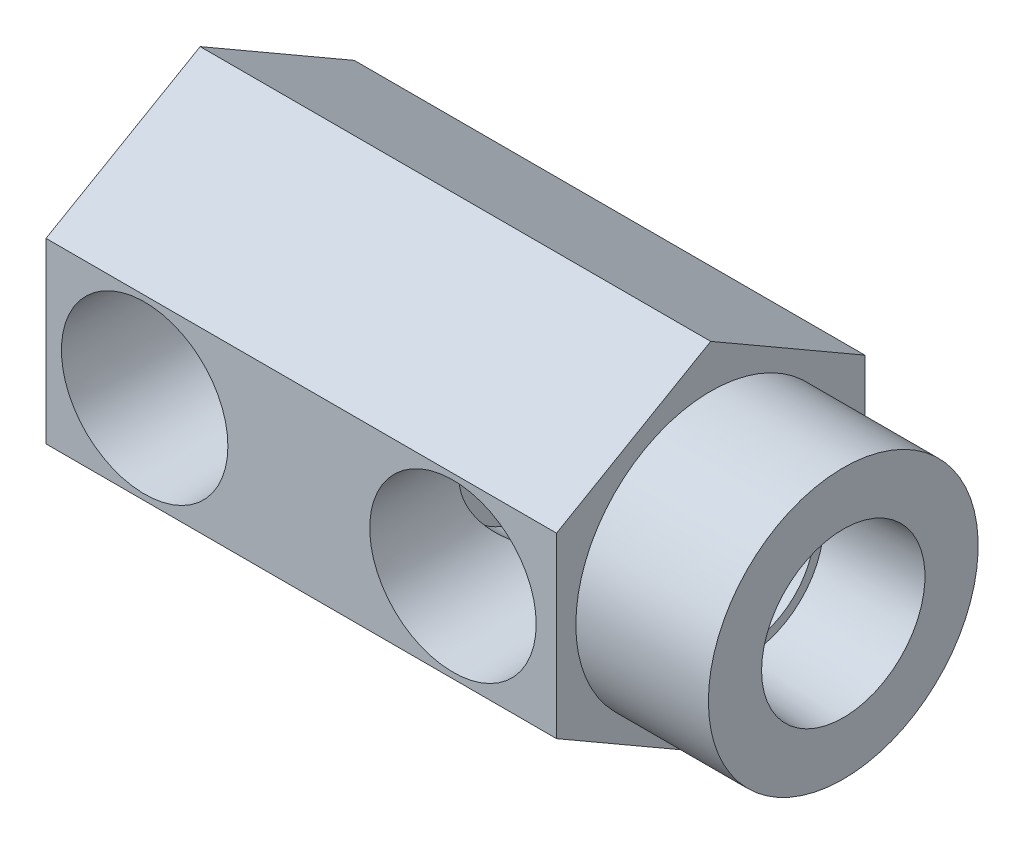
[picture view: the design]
ISO-10303-21;
HEADER;
FILE_DESCRIPTION(('STEP AP214'),'2;1');
FILE_NAME('part.step','',(''),(''),'','','');
FILE_SCHEMA(('AUTOMOTIVE_DESIGN { 1 0 10303 214 1 1 1 1 }'));
ENDSEC;
DATA;
#1=APPLICATION_CONTEXT('core data for automotive mechanical design processes');
#2=APPLICATION_PROTOCOL_DEFINITION('international standard','automotive_design',2000,#1);
#3=PRODUCT_CONTEXT('',#1,'mechanical');
#4=PRODUCT('Part','Part','',(#3));
#5=PRODUCT_RELATED_PRODUCT_CATEGORY('part','',(#4));
#6=PRODUCT_DEFINITION_FORMATION('','',#4);
#7=PRODUCT_DEFINITION_CONTEXT('part definition',#1,'design');
#8=PRODUCT_DEFINITION('design','',#6,#7);
#9=PRODUCT_DEFINITION_SHAPE('','',#8);
#10=(LENGTH_UNIT() NAMED_UNIT(*) SI_UNIT(.MILLI.,.METRE.));
#11=(NAMED_UNIT(*) PLANE_ANGLE_UNIT() SI_UNIT($,.RADIAN.));
#12=(NAMED_UNIT(*) SI_UNIT($,.STERADIAN.) SOLID_ANGLE_UNIT());
#13=UNCERTAINTY_MEASURE_WITH_UNIT(LENGTH_MEASURE(1.E-05),#10,'distance_accuracy_value','');
#14=(GEOMETRIC_REPRESENTATION_CONTEXT(3) GLOBAL_UNCERTAINTY_ASSIGNED_CONTEXT((#13)) GLOBAL_UNIT_ASSIGNED_CONTEXT((#10,
#11,#12)) REPRESENTATION_CONTEXT('',''));
#15=CARTESIAN_POINT('',(0.,0.,0.));
#16=DIRECTION('',(0.,0.,1.));
#17=DIRECTION('',(1.,0.,0.));
#18=AXIS2_PLACEMENT_3D('',#15,#16,#17);
#19=CARTESIAN_POINT('',(52.9844,0.,0.));
#20=DIRECTION('',(1.,0.,0.));
#21=DIRECTION('',(0.,0.,-1.));
#22=AXIS2_PLACEMENT_3D('',#19,#20,#21);
#23=CYLINDRICAL_SURFACE('',#22,3.17499999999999);
#24=CARTESIAN_POINT('',(16.4084,0.,0.));
#25=DIRECTION('',(1.,0.,0.));
#26=DIRECTION('',(0.,0.,-1.));
#27=AXIS2_PLACEMENT_3D('',#24,#25,#26);
#28=CIRCLE('',#27,3.17499999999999);
#29=CARTESIAN_POINT('',(16.4084,0.,-3.17499999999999));
#30=VERTEX_POINT('',#29);
#31=EDGE_CURVE('E172',#30,#30,#28,.T.);
#32=ORIENTED_EDGE('',*,*,#31,.F.);
#33=EDGE_LOOP('',(#32));
#34=FACE_BOUND('',#33,.T.);
#35=CARTESIAN_POINT('',(26.79065,0.,0.));
#36=DIRECTION('',(1.,0.,0.));
#37=DIRECTION('',(0.,0.,-1.));
#38=AXIS2_PLACEMENT_3D('',#35,#36,#37);
#39=CIRCLE('',#38,3.17499999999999);
#40=CARTESIAN_POINT('',(26.79065,0.,-3.17499999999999));
#41=VERTEX_POINT('',#40);
#42=EDGE_CURVE('E39',#41,#41,#39,.F.);
#43=ORIENTED_EDGE('',*,*,#42,.F.);
#44=EDGE_LOOP('',(#43));
#45=FACE_BOUND('',#44,.T.);
#46=ADVANCED_FACE('F35',(#34,#45),#23,.F.);
#47=CARTESIAN_POINT('',(39.0906,0.,2.6797));
#48=DIRECTION('',(0.,0.,-1.));
#49=DIRECTION('',(-1.,0.,0.));
#50=AXIS2_PLACEMENT_3D('',#47,#48,#49);
#51=PLANE('',#50);
#52=DIRECTION('',(-1.,0.,0.));
#53=VECTOR('',#52,1.);
#54=CARTESIAN_POINT('',(0.,4.86010266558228,2.6797));
#55=LINE('',#54,#53);
#56=CARTESIAN_POINT('',(37.9310089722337,4.86010266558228,2.6797));
#57=VERTEX_POINT('',#56);
#58=CARTESIAN_POINT('',(36.2339048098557,4.86010266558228,2.6797));
#59=VERTEX_POINT('',#58);
#60=EDGE_CURVE('E442',#57,#59,#55,.T.);
#61=ORIENTED_EDGE('',*,*,#60,.F.);
#62=CARTESIAN_POINT('',(33.528,0.,2.6797));
#63=DIRECTION('',(0.,0.,1.));
#64=DIRECTION('',(1.,0.,0.));
#65=AXIS2_PLACEMENT_3D('',#62,#63,#64);
#66=CIRCLE('',#65,6.55797879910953);
#67=CARTESIAN_POINT('',(29.1249910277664,4.86010266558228,2.6797));
#68=VERTEX_POINT('',#67);
#69=EDGE_CURVE('E424',#57,#68,#66,.T.);
#70=ORIENTED_EDGE('',*,*,#69,.T.);
#71=CARTESIAN_POINT('',(30.8220951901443,4.86010266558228,2.6797));
#72=VERTEX_POINT('',#71);
#73=EDGE_CURVE('E281',#72,#68,#55,.T.);
#74=ORIENTED_EDGE('',*,*,#73,.F.);
#75=CARTESIAN_POINT('',(33.528,0.,2.6797));
#76=DIRECTION('',(0.,0.,1.));
#77=DIRECTION('',(1.,0.,0.));
#78=AXIS2_PLACEMENT_3D('',#75,#76,#77);
#79=CIRCLE('',#78,5.5626);
#80=EDGE_CURVE('E164',#59,#72,#79,.T.);
#81=ORIENTED_EDGE('',*,*,#80,.F.);
#82=EDGE_LOOP('',(#61,#70,#74,#81));
#83=FACE_BOUND('',#82,.T.);
#84=ADVANCED_FACE('F261',(#83),#51,.F.);
#85=DIRECTION('',(-1.,0.,0.));
#86=VECTOR('',#85,1.);
#87=CARTESIAN_POINT('',(0.,-4.86010266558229,2.6797));
#88=LINE('',#87,#86);
#89=CARTESIAN_POINT('',(29.1249910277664,-4.86010266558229,2.6797));
#90=VERTEX_POINT('',#89);
#91=CARTESIAN_POINT('',(30.8220951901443,-4.86010266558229,2.6797));
#92=VERTEX_POINT('',#91);
#93=EDGE_CURVE('E165',#90,#92,#88,.F.);
#94=ORIENTED_EDGE('',*,*,#93,.F.);
#95=CARTESIAN_POINT('',(37.9310089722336,-4.86010266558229,2.6797));
#96=VERTEX_POINT('',#95);
#97=EDGE_CURVE('E420',#90,#96,#66,.T.);
#98=ORIENTED_EDGE('',*,*,#97,.T.);
#99=CARTESIAN_POINT('',(36.2339048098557,-4.86010266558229,2.6797));
#100=VERTEX_POINT('',#99);
#101=EDGE_CURVE('E328',#100,#96,#88,.F.);
#102=ORIENTED_EDGE('',*,*,#101,.F.);
#103=EDGE_CURVE('E430',#92,#100,#79,.T.);
#104=ORIENTED_EDGE('',*,*,#103,.F.);
#105=EDGE_LOOP('',(#94,#98,#102,#104));
#106=FACE_BOUND('',#105,.T.);
#107=ADVANCED_FACE('F331',(#106),#51,.F.);
#108=CARTESIAN_POINT('',(33.528,0.,12.7));
#109=DIRECTION('',(0.,0.,1.));
#110=DIRECTION('',(1.,0.,0.));
#111=AXIS2_PLACEMENT_3D('',#108,#109,#110);
#112=CYLINDRICAL_SURFACE('',#111,5.56260000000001);
#113=CARTESIAN_POINT('',(29.1430778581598,3.42271479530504,-4.3688));
#114=CARTESIAN_POINT('',(29.2053786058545,3.50252392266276,-4.30626922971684));
#115=CARTESIAN_POINT('',(29.2692305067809,3.57983993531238,-4.24217199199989));
#116=CARTESIAN_POINT('',(29.3997001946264,3.72954742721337,-4.111175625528));
#117=CARTESIAN_POINT('',(29.4663169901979,3.80194064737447,-4.0442775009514));
#118=CARTESIAN_POINT('',(29.6696020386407,4.01162562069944,-3.84008739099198));
#119=CARTESIAN_POINT('',(29.8099614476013,4.14174719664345,-3.69904228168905));
#120=CARTESIAN_POINT('',(30.0975597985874,4.38288342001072,-3.40984184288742));
#121=CARTESIAN_POINT('',(30.2447640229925,4.4939834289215,-3.26172230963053));
#122=CARTESIAN_POINT('',(30.5450099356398,4.69864874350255,-2.95929639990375));
#123=CARTESIAN_POINT('',(30.6980539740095,4.79220689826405,-2.80498753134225));
#124=CARTESIAN_POINT('',(30.9831508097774,4.94855700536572,-2.51703491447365));
#125=CARTESIAN_POINT('',(31.1145644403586,5.01387804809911,-2.38411695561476));
#126=CARTESIAN_POINT('',(31.3796036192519,5.13303105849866,-2.11541586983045));
#127=CARTESIAN_POINT('',(31.5132288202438,5.1868648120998,-1.97963319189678));
#128=CARTESIAN_POINT('',(31.7816711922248,5.28329287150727,-1.7056562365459));
#129=CARTESIAN_POINT('',(31.9164866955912,5.32590091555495,-1.56746512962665));
#130=CARTESIAN_POINT('',(32.1863893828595,5.40019502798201,-1.28848056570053));
#131=CARTESIAN_POINT('',(32.3214764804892,5.43188413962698,-1.14768784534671));
#132=CARTESIAN_POINT('',(32.5189904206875,5.47070908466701,-0.936746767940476));
#133=CARTESIAN_POINT('',(32.5823943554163,5.48200911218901,-0.868244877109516));
#134=CARTESIAN_POINT('',(32.7080219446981,5.50219723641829,-0.729494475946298));
#135=CARTESIAN_POINT('',(32.7702429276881,5.51108036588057,-0.659242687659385));
#136=CARTESIAN_POINT('',(32.878517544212,5.5247658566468,-0.530668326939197));
#137=CARTESIAN_POINT('',(32.9252277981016,5.53003323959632,-0.4729291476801));
#138=CARTESIAN_POINT('',(33.0138391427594,5.53895660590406,-0.353523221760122));
#139=CARTESIAN_POINT('',(33.0557550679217,5.54261766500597,-0.291869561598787));
#140=CARTESIAN_POINT('',(33.1029068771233,5.54635110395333,-0.200071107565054));
#141=CARTESIAN_POINT('',(33.1149282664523,5.54725075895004,-0.17362424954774));
#142=CARTESIAN_POINT('',(33.1346806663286,5.54868581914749,-0.11920938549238));
#143=CARTESIAN_POINT('',(33.1424339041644,5.54922311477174,-0.091250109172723));
#144=CARTESIAN_POINT('',(33.1507682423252,5.54979551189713,-0.0406082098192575));
#145=CARTESIAN_POINT('',(33.1525611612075,5.54991574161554,-0.0181354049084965));
#146=CARTESIAN_POINT('',(33.1520473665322,5.5498809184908,0.0267461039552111));
#147=CARTESIAN_POINT('',(33.1497432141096,5.54972603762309,0.0491548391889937));
#148=CARTESIAN_POINT('',(33.1402182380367,5.54906942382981,0.100345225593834));
#149=CARTESIAN_POINT('',(33.1316568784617,5.54847233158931,0.128864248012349));
#150=CARTESIAN_POINT('',(33.1103226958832,5.54690714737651,0.184367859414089));
#151=CARTESIAN_POINT('',(33.0975213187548,5.54593653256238,0.21134054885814));
#152=CARTESIAN_POINT('',(33.0586644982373,5.54281975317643,0.284099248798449));
#153=CARTESIAN_POINT('',(33.0299816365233,5.5403433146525,0.328420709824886));
#154=CARTESIAN_POINT('',(32.9692649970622,5.5345538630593,0.414689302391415));
#155=CARTESIAN_POINT('',(32.9372207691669,5.53123819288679,0.456628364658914));
#156=CARTESIAN_POINT('',(32.8710999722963,5.52377748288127,0.539458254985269));
#157=CARTESIAN_POINT('',(32.8370069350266,5.51962483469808,0.580335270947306));
#158=CARTESIAN_POINT('',(32.7679056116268,5.51053473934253,0.661091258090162));
#159=CARTESIAN_POINT('',(32.7328988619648,5.50559854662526,0.700971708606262));
#160=CARTESIAN_POINT('',(32.6194514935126,5.48846855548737,0.828218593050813));
#161=CARTESIAN_POINT('',(32.5399173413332,5.47474378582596,0.914407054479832));
#162=CARTESIAN_POINT('',(32.3799423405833,5.44345110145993,1.08523802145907));
#163=CARTESIAN_POINT('',(32.2995012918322,5.42588232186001,1.16988017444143));
#164=CARTESIAN_POINT('',(32.0576616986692,5.36731988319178,1.4223942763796));
#165=CARTESIAN_POINT('',(31.8959389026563,5.32049832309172,1.58864694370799));
#166=CARTESIAN_POINT('',(31.5803741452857,5.21306486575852,1.91130379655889));
#167=CARTESIAN_POINT('',(31.4264669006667,5.15304719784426,2.06784173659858));
#168=CARTESIAN_POINT('',(31.1978738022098,5.05172859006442,2.29968019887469));
#169=CARTESIAN_POINT('',(31.1221017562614,5.01610006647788,2.37641685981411));
#170=CARTESIAN_POINT('',(30.9714170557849,4.94100069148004,2.52885627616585));
#171=CARTESIAN_POINT('',(30.89650445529,4.90152959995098,2.60455896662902));
#172=CARTESIAN_POINT('',(30.8220951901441,4.8601026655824,2.67969999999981));
#173=B_SPLINE_CURVE_WITH_KNOTS('',3,(#113,#114,#115,#116,#117,#118,#119,#120,#121,#122,#123,
#124,#125,#126,#127,#128,#129,#130,#131,#132,#133,#134,#135,#136,#137,#138,#139,#140,#141,#142,
#143,#144,#145,#146,#147,#148,#149,#150,#151,#152,#153,#154,#155,#156,#157,#158,#159,#160,#161,
#162,#163,#164,#165,#166,#167,#168,#169,#170,#171,#172),.UNSPECIFIED.,.F.,.F.,(4,2,2,2,2,2,2,2,
2,2,2,2,2,2,2,2,2,2,2,2,2,2,2,2,2,2,2,2,2,4),(0.,0.356890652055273,0.713654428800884,
1.42572741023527,2.13451598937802,2.84359287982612,3.4372250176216,4.03076479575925,
4.6235747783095,5.2162194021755,5.49827347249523,5.78090291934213,6.00433449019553,
6.22705487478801,6.3140330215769,6.40055381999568,6.46782718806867,6.53505851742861,
6.62386536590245,6.71328286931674,6.87138898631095,7.03000208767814,7.19012792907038,
7.34999994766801,7.70411945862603,8.05831872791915,8.7675669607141,9.44975807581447,
9.7904185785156,10.1311003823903),.UNSPECIFIED.);
#174=CARTESIAN_POINT('',(29.1430778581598,3.42271479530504,-4.3688));
#175=VERTEX_POINT('',#174);
#176=EDGE_CURVE('E150',#175,#72,#173,.T.);
#177=ORIENTED_EDGE('',*,*,#176,.F.);
#178=CARTESIAN_POINT('',(33.528,0.,-4.3688));
#179=DIRECTION('',(0.,0.,1.));
#180=DIRECTION('',(1.,0.,0.));
#181=AXIS2_PLACEMENT_3D('',#178,#179,#180);
#182=CIRCLE('',#181,5.56260000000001);
#183=CARTESIAN_POINT('',(37.9129221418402,3.42271479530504,-4.3688));
#184=VERTEX_POINT('',#183);
#185=EDGE_CURVE('E162',#184,#175,#182,.T.);
#186=ORIENTED_EDGE('',*,*,#185,.F.);
#187=CARTESIAN_POINT('',(36.2339048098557,4.86010266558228,2.6797));
#188=CARTESIAN_POINT('',(36.1573626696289,4.90271691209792,2.6024048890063));
#189=CARTESIAN_POINT('',(36.0802883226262,4.94326160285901,2.52451611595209));
#190=CARTESIAN_POINT('',(35.9252343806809,5.02028696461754,2.36764700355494));
#191=CARTESIAN_POINT('',(35.8472548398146,5.05676787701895,2.28866672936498));
#192=CARTESIAN_POINT('',(35.6120714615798,5.16028405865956,2.05010484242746));
#193=CARTESIAN_POINT('',(35.4537326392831,5.22133212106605,1.88901283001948));
#194=CARTESIAN_POINT('',(35.1345730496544,5.32821249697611,1.56246076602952));
#195=CARTESIAN_POINT('',(34.9737434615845,5.37396013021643,1.39698170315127));
#196=CARTESIAN_POINT('',(34.7333316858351,5.43106765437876,1.14553430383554));
#197=CARTESIAN_POINT('',(34.6533574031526,5.44818105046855,1.06120651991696));
#198=CARTESIAN_POINT('',(34.4943992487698,5.47860389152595,0.890954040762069));
#199=CARTESIAN_POINT('',(34.4154151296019,5.49191430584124,0.805029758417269));
#200=CARTESIAN_POINT('',(34.2931936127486,5.50990529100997,0.667021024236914));
#201=CARTESIAN_POINT('',(34.2489571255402,5.51585557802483,0.615983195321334));
#202=CARTESIAN_POINT('',(34.1624383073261,5.52647109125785,0.512104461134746));
#203=CARTESIAN_POINT('',(34.1201555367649,5.5311366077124,0.459263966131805));
#204=CARTESIAN_POINT('',(34.0564332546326,5.53749527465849,0.372271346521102));
#205=CARTESIAN_POINT('',(34.033506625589,5.53962582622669,0.339251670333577));
#206=CARTESIAN_POINT('',(33.9905937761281,5.54337271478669,0.271242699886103));
#207=CARTESIAN_POINT('',(33.9706061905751,5.54498929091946,0.236254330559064));
#208=CARTESIAN_POINT('',(33.9426831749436,5.54713245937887,0.176754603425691));
#209=CARTESIAN_POINT('',(33.933013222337,5.54784146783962,0.153090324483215));
#210=CARTESIAN_POINT('',(33.9172951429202,5.54896659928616,0.104612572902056));
#211=CARTESIAN_POINT('',(33.9112335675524,5.54938381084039,0.0798037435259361));
#212=CARTESIAN_POINT('',(33.9039509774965,5.54988255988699,0.029035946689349));
#213=CARTESIAN_POINT('',(33.9028053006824,5.54995887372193,0.00306520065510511));
#214=CARTESIAN_POINT('',(33.9059120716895,5.54974795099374,-0.0485454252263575));
#215=CARTESIAN_POINT('',(33.9101699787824,5.54946034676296,-0.0741849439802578));
#216=CARTESIAN_POINT('',(33.9247955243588,5.54843534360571,-0.131549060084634));
#217=CARTESIAN_POINT('',(33.9365743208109,5.54759189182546,-0.162888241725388));
#218=CARTESIAN_POINT('',(33.9643836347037,5.54547446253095,-0.223685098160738));
#219=CARTESIAN_POINT('',(33.9804398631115,5.54419786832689,-0.25313001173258));
#220=CARTESIAN_POINT('',(34.0343579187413,5.53962508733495,-0.343123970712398));
#221=CARTESIAN_POINT('',(34.0763107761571,5.5356796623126,-0.40110731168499));
#222=CARTESIAN_POINT('',(34.1638595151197,5.52631907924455,-0.51417606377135));
#223=CARTESIAN_POINT('',(34.2094670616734,5.52089907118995,-0.569251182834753));
#224=CARTESIAN_POINT('',(34.3026304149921,5.50860024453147,-0.678027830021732));
#225=CARTESIAN_POINT('',(34.350194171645,5.50171487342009,-0.731721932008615));
#226=CARTESIAN_POINT('',(34.4461025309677,5.48652622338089,-0.838028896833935));
#227=CARTESIAN_POINT('',(34.4944457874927,5.47822519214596,-0.890643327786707));
#228=CARTESIAN_POINT('',(34.6402922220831,5.45115530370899,-1.04766823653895));
#229=CARTESIAN_POINT('',(34.7384665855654,5.43023844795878,-1.15109678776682));
#230=CARTESIAN_POINT('',(34.9351156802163,5.38263989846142,-1.35633654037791));
#231=CARTESIAN_POINT('',(35.033590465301,5.35595710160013,-1.45814742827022));
#232=CARTESIAN_POINT('',(35.3287530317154,5.26707075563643,-1.76179770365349));
#233=CARTESIAN_POINT('',(35.5249600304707,5.19606887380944,-1.96162494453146));
#234=CARTESIAN_POINT('',(35.9119743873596,5.03024468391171,-2.35440015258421));
#235=CARTESIAN_POINT('',(36.1028039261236,4.93554387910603,-2.54737764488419));
#236=CARTESIAN_POINT('',(36.4776329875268,4.72109486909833,-2.92572825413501));
#237=CARTESIAN_POINT('',(36.6616385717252,4.60136955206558,-3.11110813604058));
#238=CARTESIAN_POINT('',(36.9369676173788,4.39724605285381,-3.38822135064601));
#239=CARTESIAN_POINT('',(37.0317095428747,4.3222036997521,-3.48352487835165));
#240=CARTESIAN_POINT('',(37.2179314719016,4.1643506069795,-3.67077145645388));
#241=CARTESIAN_POINT('',(37.3094126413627,4.08154268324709,-3.76271570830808));
#242=CARTESIAN_POINT('',(37.488908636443,3.90760849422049,-3.94306288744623));
#243=CARTESIAN_POINT('',(37.5769089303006,3.81645174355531,-4.03145099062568));
#244=CARTESIAN_POINT('',(37.748455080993,3.62583915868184,-4.20370936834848));
#245=CARTESIAN_POINT('',(37.8319969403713,3.52637607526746,-4.28757558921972));
#246=CARTESIAN_POINT('',(37.9129221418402,3.42271479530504,-4.3688));
#247=B_SPLINE_CURVE_WITH_KNOTS('',3,(#187,#188,#189,#190,#191,#192,#193,#194,#195,#196,#197,
#198,#199,#200,#201,#202,#203,#204,#205,#206,#207,#208,#209,#210,#211,#212,#213,#214,#215,#216,
#217,#218,#219,#220,#221,#222,#223,#224,#225,#226,#227,#228,#229,#230,#231,#232,#233,#234,#235,
#236,#237,#238,#239,#240,#241,#242,#243,#244,#245,#246),.UNSPECIFIED.,.F.,.F.,(4,2,2,2,2,2,2,2,
2,2,2,2,2,2,2,2,2,2,2,2,2,2,2,2,2,2,2,2,2,4),(0.,0.350444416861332,0.700868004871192,
1.4022157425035,2.10738322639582,2.45975259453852,2.8120320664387,3.01541959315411,
3.21876113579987,3.33946287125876,3.46010836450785,3.53663938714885,3.61288336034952,
3.69029171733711,3.7677783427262,3.8676813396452,3.9681989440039,4.18262718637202,
4.39776940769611,4.61389466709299,4.82967991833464,5.26190889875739,5.69422064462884,
6.55980087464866,7.42103111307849,8.28147706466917,8.74300288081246,9.20436198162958,
9.66747853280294,10.1310035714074),.UNSPECIFIED.);
#248=EDGE_CURVE('E58',#59,#184,#247,.T.);
#249=ORIENTED_EDGE('',*,*,#248,.F.);
#250=ORIENTED_EDGE('',*,*,#80,.T.);
#251=EDGE_LOOP('',(#177,#186,#249,#250));
#252=FACE_BOUND('',#251,.T.);
#253=ADVANCED_FACE('F161',(#252),#112,.F.);
#254=CARTESIAN_POINT('',(37.9129221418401,-3.42271479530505,-4.3688));
#255=CARTESIAN_POINT('',(37.8506213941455,-3.50252392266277,-4.30626922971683));
#256=CARTESIAN_POINT('',(37.7867694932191,-3.57983993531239,-4.24217199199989));
#257=CARTESIAN_POINT('',(37.6562998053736,-3.72954742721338,-4.111175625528));
#258=CARTESIAN_POINT('',(37.5896830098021,-3.80194064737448,-4.0442775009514));
#259=CARTESIAN_POINT('',(37.3863979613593,-4.01162562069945,-3.84008739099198));
#260=CARTESIAN_POINT('',(37.2460385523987,-4.14174719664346,-3.69904228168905));
#261=CARTESIAN_POINT('',(36.9584402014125,-4.38288342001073,-3.40984184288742));
#262=CARTESIAN_POINT('',(36.8112359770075,-4.49398342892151,-3.26172230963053));
#263=CARTESIAN_POINT('',(36.5109900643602,-4.69864874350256,-2.95929639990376));
#264=CARTESIAN_POINT('',(36.3579460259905,-4.79220689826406,-2.80498753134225));
#265=CARTESIAN_POINT('',(36.0728491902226,-4.94855700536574,-2.51703491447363));
#266=CARTESIAN_POINT('',(35.9414355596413,-5.01387804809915,-2.38411695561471));
#267=CARTESIAN_POINT('',(35.676396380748,-5.13303105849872,-2.11541586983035));
#268=CARTESIAN_POINT('',(35.5427711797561,-5.18686481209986,-1.97963319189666));
#269=CARTESIAN_POINT('',(35.274328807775,-5.28329287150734,-1.70565623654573));
#270=CARTESIAN_POINT('',(35.1395133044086,-5.32590091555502,-1.56746512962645));
#271=CARTESIAN_POINT('',(34.8696106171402,-5.40019502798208,-1.28848056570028));
#272=CARTESIAN_POINT('',(34.7345235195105,-5.43188413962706,-1.14768784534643));
#273=CARTESIAN_POINT('',(34.5370095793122,-5.47070908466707,-0.936746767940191));
#274=CARTESIAN_POINT('',(34.4736056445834,-5.48200911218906,-0.868244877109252));
#275=CARTESIAN_POINT('',(34.3479780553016,-5.50219723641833,-0.729494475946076));
#276=CARTESIAN_POINT('',(34.2857570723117,-5.51108036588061,-0.659242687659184));
#277=CARTESIAN_POINT('',(34.1774824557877,-5.52476585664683,-0.530668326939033));
#278=CARTESIAN_POINT('',(34.1307722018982,-5.53003323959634,-0.472929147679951));
#279=CARTESIAN_POINT('',(34.0421608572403,-5.53895660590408,-0.353523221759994));
#280=CARTESIAN_POINT('',(34.0002449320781,-5.54261766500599,-0.291869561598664));
#281=CARTESIAN_POINT('',(33.9530931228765,-5.54635110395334,-0.200071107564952));
#282=CARTESIAN_POINT('',(33.9410717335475,-5.54725075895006,-0.173624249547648));
#283=CARTESIAN_POINT('',(33.9213193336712,-5.5486858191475,-0.119209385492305));
#284=CARTESIAN_POINT('',(33.9135660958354,-5.54922311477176,-0.0912501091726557));
#285=CARTESIAN_POINT('',(33.9052317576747,-5.54979551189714,-0.040608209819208));
#286=CARTESIAN_POINT('',(33.9034388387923,-5.54991574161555,-0.0181354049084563));
#287=CARTESIAN_POINT('',(33.9039526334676,-5.54988091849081,0.0267461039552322));
#288=CARTESIAN_POINT('',(33.9062567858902,-5.5497260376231,0.049154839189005));
#289=CARTESIAN_POINT('',(33.9157817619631,-5.54906942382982,0.100345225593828));
#290=CARTESIAN_POINT('',(33.9243431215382,-5.54847233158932,0.128864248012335));
#291=CARTESIAN_POINT('',(33.9456773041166,-5.54690714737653,0.184367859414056));
#292=CARTESIAN_POINT('',(33.9584786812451,-5.54593653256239,0.211340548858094));
#293=CARTESIAN_POINT('',(33.9973355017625,-5.54281975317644,0.284099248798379));
#294=CARTESIAN_POINT('',(34.0260183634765,-5.54034331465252,0.328420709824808));
#295=CARTESIAN_POINT('',(34.0867350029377,-5.53455386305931,0.414689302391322));
#296=CARTESIAN_POINT('',(34.1187792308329,-5.53123819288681,0.456628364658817));
#297=CARTESIAN_POINT('',(34.1849000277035,-5.5237774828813,0.539458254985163));
#298=CARTESIAN_POINT('',(34.2189930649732,-5.5196248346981,0.580335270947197));
#299=CARTESIAN_POINT('',(34.288094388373,-5.51053473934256,0.66109125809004));
#300=CARTESIAN_POINT('',(34.323101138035,-5.50559854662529,0.700971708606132));
#301=CARTESIAN_POINT('',(34.4365485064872,-5.4884685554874,0.828218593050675));
#302=CARTESIAN_POINT('',(34.5160826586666,-5.474743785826,0.914407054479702));
#303=CARTESIAN_POINT('',(34.6760576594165,-5.44345110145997,1.08523802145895));
#304=CARTESIAN_POINT('',(34.7564987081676,-5.42588232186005,1.16988017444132));
#305=CARTESIAN_POINT('',(34.9983383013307,-5.36731988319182,1.4223942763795));
#306=CARTESIAN_POINT('',(35.1600610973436,-5.32049832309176,1.58864694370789));
#307=CARTESIAN_POINT('',(35.4756258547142,-5.21306486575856,1.91130379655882));
#308=CARTESIAN_POINT('',(35.6295330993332,-5.1530471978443,2.06784173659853));
#309=CARTESIAN_POINT('',(35.8581261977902,-5.05172859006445,2.29968019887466));
#310=CARTESIAN_POINT('',(35.9338982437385,-5.0161000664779,2.37641685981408));
#311=CARTESIAN_POINT('',(36.084582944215,-4.94100069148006,2.52885627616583));
#312=CARTESIAN_POINT('',(36.1594955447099,-4.901529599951,2.60455896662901));
#313=CARTESIAN_POINT('',(36.2339048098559,-4.86010266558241,2.67969999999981));
#314=B_SPLINE_CURVE_WITH_KNOTS('',3,(#254,#255,#256,#257,#258,#259,#260,#261,#262,#263,#264,
#265,#266,#267,#268,#269,#270,#271,#272,#273,#274,#275,#276,#277,#278,#279,#280,#281,#282,#283,
#284,#285,#286,#287,#288,#289,#290,#291,#292,#293,#294,#295,#296,#297,#298,#299,#300,#301,#302,
#303,#304,#305,#306,#307,#308,#309,#310,#311,#312,#313),.UNSPECIFIED.,.F.,.F.,(4,2,2,2,2,2,2,2,
2,2,2,2,2,2,2,2,2,2,2,2,2,2,2,2,2,2,2,2,2,4),(0.,0.356890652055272,0.713654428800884,
1.42572741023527,2.13451598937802,2.84359287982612,3.43722501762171,4.03076479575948,
4.62357477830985,5.21621940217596,5.49827347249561,5.78090291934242,6.00433449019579,
6.22705487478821,6.31403302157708,6.40055381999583,6.4678271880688,6.53505851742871,
6.62386536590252,6.71328286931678,6.87138898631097,7.03000208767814,7.19012792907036,
7.34999994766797,7.70411945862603,8.05831872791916,8.76756696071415,9.44975807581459,
9.79041857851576,10.1311003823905),.UNSPECIFIED.);
#315=CARTESIAN_POINT('',(37.9129221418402,-3.42271479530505,-4.3688));
#316=VERTEX_POINT('',#315);
#317=EDGE_CURVE('E323',#316,#100,#314,.T.);
#318=ORIENTED_EDGE('',*,*,#317,.F.);
#319=CARTESIAN_POINT('',(29.1430778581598,-3.42271479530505,-4.3688));
#320=VERTEX_POINT('',#319);
#321=EDGE_CURVE('E169',#320,#316,#182,.T.);
#322=ORIENTED_EDGE('',*,*,#321,.F.);
#323=CARTESIAN_POINT('',(30.8220951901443,-4.86010266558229,2.6797));
#324=CARTESIAN_POINT('',(30.8986373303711,-4.90271691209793,2.6024048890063));
#325=CARTESIAN_POINT('',(30.9757116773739,-4.94326160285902,2.52451611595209));
#326=CARTESIAN_POINT('',(31.1307656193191,-5.02028696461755,2.36764700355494));
#327=CARTESIAN_POINT('',(31.2087451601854,-5.05676787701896,2.28866672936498));
#328=CARTESIAN_POINT('',(31.4439285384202,-5.16028405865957,2.05010484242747));
#329=CARTESIAN_POINT('',(31.6022673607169,-5.22133212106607,1.88901283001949));
#330=CARTESIAN_POINT('',(31.9214269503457,-5.32821249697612,1.56246076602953));
#331=CARTESIAN_POINT('',(32.0822565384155,-5.37396013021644,1.39698170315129));
#332=CARTESIAN_POINT('',(32.3226683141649,-5.43106765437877,1.14553430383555));
#333=CARTESIAN_POINT('',(32.4026425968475,-5.44818105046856,1.06120651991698));
#334=CARTESIAN_POINT('',(32.5616007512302,-5.47860389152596,0.890954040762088));
#335=CARTESIAN_POINT('',(32.6405848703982,-5.49191430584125,0.805029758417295));
#336=CARTESIAN_POINT('',(32.7628063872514,-5.50990529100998,0.667021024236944));
#337=CARTESIAN_POINT('',(32.8070428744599,-5.51585557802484,0.615983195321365));
#338=CARTESIAN_POINT('',(32.8935616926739,-5.52647109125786,0.512104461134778));
#339=CARTESIAN_POINT('',(32.9358444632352,-5.53113660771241,0.459263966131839));
#340=CARTESIAN_POINT('',(32.9995667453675,-5.53749527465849,0.372271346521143));
#341=CARTESIAN_POINT('',(33.0224933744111,-5.5396258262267,0.339251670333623));
#342=CARTESIAN_POINT('',(33.065406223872,-5.5433727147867,0.271242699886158));
#343=CARTESIAN_POINT('',(33.085393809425,-5.54498929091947,0.236254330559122));
#344=CARTESIAN_POINT('',(33.1133168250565,-5.54713245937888,0.176754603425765));
#345=CARTESIAN_POINT('',(33.1229867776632,-5.54784146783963,0.153090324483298));
#346=CARTESIAN_POINT('',(33.1387048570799,-5.54896659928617,0.104612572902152));
#347=CARTESIAN_POINT('',(33.1447664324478,-5.54938381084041,0.0798037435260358));
#348=CARTESIAN_POINT('',(33.1520490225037,-5.549882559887,0.0290359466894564));
#349=CARTESIAN_POINT('',(33.1531946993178,-5.54995887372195,0.00306520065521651));
#350=CARTESIAN_POINT('',(33.1500879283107,-5.54974795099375,-0.0485454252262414));
#351=CARTESIAN_POINT('',(33.1458300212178,-5.54946034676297,-0.0741849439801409));
#352=CARTESIAN_POINT('',(33.1312044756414,-5.54843534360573,-0.13154906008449));
#353=CARTESIAN_POINT('',(33.1194256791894,-5.54759189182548,-0.162888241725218));
#354=CARTESIAN_POINT('',(33.0916163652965,-5.54547446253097,-0.223685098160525));
#355=CARTESIAN_POINT('',(33.0755601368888,-5.54419786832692,-0.253130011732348));
#356=CARTESIAN_POINT('',(33.0216420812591,-5.53962508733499,-0.343123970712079));
#357=CARTESIAN_POINT('',(32.9796892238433,-5.53567966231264,-0.401107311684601));
#358=CARTESIAN_POINT('',(32.8921404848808,-5.52631907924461,-0.514176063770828));
#359=CARTESIAN_POINT('',(32.8465329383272,-5.52089907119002,-0.569251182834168));
#360=CARTESIAN_POINT('',(32.7533695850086,-5.50860024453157,-0.678027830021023));
#361=CARTESIAN_POINT('',(32.7058058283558,-5.50171487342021,-0.731721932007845));
#362=CARTESIAN_POINT('',(32.6098974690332,-5.48652622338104,-0.838028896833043));
#363=CARTESIAN_POINT('',(32.5615542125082,-5.47822519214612,-0.890643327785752));
#364=CARTESIAN_POINT('',(32.4157077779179,-5.4511553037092,-1.04766823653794));
#365=CARTESIAN_POINT('',(32.3175334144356,-5.430238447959,-1.15109678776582));
#366=CARTESIAN_POINT('',(32.1208843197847,-5.38263989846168,-1.35633654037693));
#367=CARTESIAN_POINT('',(32.0224095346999,-5.35595710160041,-1.45814742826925));
#368=CARTESIAN_POINT('',(31.7272469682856,-5.26707075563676,-1.76179770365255));
#369=CARTESIAN_POINT('',(31.5310399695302,-5.1960688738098,-1.96162494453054));
#370=CARTESIAN_POINT('',(31.1440256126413,-5.03024468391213,-2.35440015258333));
#371=CARTESIAN_POINT('',(30.9531960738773,-4.93554387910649,-2.54737764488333));
#372=CARTESIAN_POINT('',(30.578367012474,-4.72109486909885,-2.92572825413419));
#373=CARTESIAN_POINT('',(30.3943614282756,-4.60136955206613,-3.11110813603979));
#374=CARTESIAN_POINT('',(30.1190323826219,-4.39724605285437,-3.38822135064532));
#375=CARTESIAN_POINT('',(30.024290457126,-4.32220369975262,-3.48352487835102));
#376=CARTESIAN_POINT('',(29.838068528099,-4.16435060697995,-3.67077145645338));
#377=CARTESIAN_POINT('',(29.7465873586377,-4.0815426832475,-3.76271570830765));
#378=CARTESIAN_POINT('',(29.5670913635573,-3.9076084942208,-3.94306288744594));
#379=CARTESIAN_POINT('',(29.4790910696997,-3.81645174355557,-4.03145099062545));
#380=CARTESIAN_POINT('',(29.3075449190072,-3.62583915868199,-4.20370936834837));
#381=CARTESIAN_POINT('',(29.2240030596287,-3.52637607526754,-4.28757558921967));
#382=CARTESIAN_POINT('',(29.1430778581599,-3.42271479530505,-4.3688));
#383=B_SPLINE_CURVE_WITH_KNOTS('',3,(#323,#324,#325,#326,#327,#328,#329,#330,#331,#332,#333,
#334,#335,#336,#337,#338,#339,#340,#341,#342,#343,#344,#345,#346,#347,#348,#349,#350,#351,#352,
#353,#354,#355,#356,#357,#358,#359,#360,#361,#362,#363,#364,#365,#366,#367,#368,#369,#370,#371,
#372,#373,#374,#375,#376,#377,#378,#379,#380,#381,#382),.UNSPECIFIED.,.F.,.F.,(4,2,2,2,2,2,2,2,
2,2,2,2,2,2,2,2,2,2,2,2,2,2,2,2,2,2,2,2,2,4),(0.,0.350444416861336,0.700868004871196,
1.4022157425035,2.10738322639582,2.45975259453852,2.8120320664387,3.01541959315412,
3.21876113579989,3.33946287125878,3.46010836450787,3.53663938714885,3.61288336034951,
3.69029171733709,3.76777834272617,3.86768133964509,3.96819894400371,4.18262718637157,
4.3977694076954,4.61389466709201,4.8296799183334,5.26190889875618,5.69422064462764,
6.55980087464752,7.42103111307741,8.28147706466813,8.74300288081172,9.20436198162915,
9.66747853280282,10.1310035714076),.UNSPECIFIED.);
#384=EDGE_CURVE('E51',#92,#320,#383,.T.);
#385=ORIENTED_EDGE('',*,*,#384,.F.);
#386=ORIENTED_EDGE('',*,*,#103,.T.);
#387=EDGE_LOOP('',(#318,#322,#385,#386));
#388=FACE_BOUND('',#387,.T.);
#389=ADVANCED_FACE('F259',(#388),#112,.F.);
#390=CARTESIAN_POINT('',(33.528,0.,12.7));
#391=DIRECTION('',(0.,0.,1.));
#392=DIRECTION('',(1.,0.,0.));
#393=AXIS2_PLACEMENT_3D('',#390,#391,#392);
#394=CONICAL_SURFACE('',#393,6.858,0.0299323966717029);
#395=CARTESIAN_POINT('',(33.528,0.,12.7));
#396=DIRECTION('',(0.,0.,1.));
#397=DIRECTION('',(1.,0.,0.));
#398=AXIS2_PLACEMENT_3D('',#395,#396,#397);
#399=CIRCLE('',#398,6.858);
#400=CARTESIAN_POINT('',(40.386,0.,12.7));
#401=VERTEX_POINT('',#400);
#402=EDGE_CURVE('E419',#401,#401,#399,.T.);
#403=ORIENTED_EDGE('',*,*,#402,.T.);
#404=EDGE_LOOP('',(#403));
#405=FACE_BOUND('',#404,.T.);
#406=CARTESIAN_POINT('',(37.9308783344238,-4.86021293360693,2.6795));
#407=CARTESIAN_POINT('',(37.9796010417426,-4.81909090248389,2.75408000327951));
#408=CARTESIAN_POINT('',(38.0286598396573,-4.77636003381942,2.82753681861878));
#409=CARTESIAN_POINT('',(38.1271327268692,-4.68768621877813,2.97223805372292));
#410=CARTESIAN_POINT('',(38.1765468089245,-4.64174333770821,3.04348251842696));
#411=CARTESIAN_POINT('',(38.3249383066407,-4.4990172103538,3.25407862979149));
#412=CARTESIAN_POINT('',(38.4239764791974,-4.3974102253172,3.39015939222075));
#413=CARTESIAN_POINT('',(38.6208561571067,-4.1803388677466,3.65453950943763));
#414=CARTESIAN_POINT('',(38.7186784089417,-4.06475615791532,3.78275622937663));
#415=CARTESIAN_POINT('',(38.9100637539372,-3.82049762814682,4.029307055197));
#416=CARTESIAN_POINT('',(39.0036289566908,-3.69182839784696,4.14764608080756));
#417=CARTESIAN_POINT('',(39.2343157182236,-3.34676203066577,4.43565665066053));
#418=CARTESIAN_POINT('',(39.3671686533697,-3.12096559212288,4.5978682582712));
#419=CARTESIAN_POINT('',(39.5489763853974,-2.75981236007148,4.81711655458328));
#420=CARTESIAN_POINT('',(39.6066004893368,-2.63586854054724,4.88611027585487));
#421=CARTESIAN_POINT('',(39.7151484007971,-2.38067403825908,5.01539772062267));
#422=CARTESIAN_POINT('',(39.7660734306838,-2.24942469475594,5.07569303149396));
#423=CARTESIAN_POINT('',(39.8520863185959,-2.00333052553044,5.17712379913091));
#424=CARTESIAN_POINT('',(39.8883924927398,-1.88953159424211,5.21977180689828));
#425=CARTESIAN_POINT('',(39.9550956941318,-1.65782803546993,5.29791803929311));
#426=CARTESIAN_POINT('',(39.9854939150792,-1.53992424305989,5.33341770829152));
#427=CARTESIAN_POINT('',(40.0398569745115,-1.30057990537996,5.39677782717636));
#428=CARTESIAN_POINT('',(40.063819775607,-1.17913825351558,5.42463585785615));
#429=CARTESIAN_POINT('',(40.1048268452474,-0.933578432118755,5.47224389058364));
#430=CARTESIAN_POINT('',(40.1218743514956,-0.809461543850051,5.49199768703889));
#431=CARTESIAN_POINT('',(40.1487709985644,-0.55885523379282,5.5231405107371));
#432=CARTESIAN_POINT('',(40.1585888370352,-0.432357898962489,5.53449316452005));
#433=CARTESIAN_POINT('',(40.1706904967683,-0.178520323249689,5.5484842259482));
#434=CARTESIAN_POINT('',(40.172974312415,-0.0511800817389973,5.55112262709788));
#435=CARTESIAN_POINT('',(40.1699567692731,0.203283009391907,5.54763517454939));
#436=CARTESIAN_POINT('',(40.16465579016,0.330405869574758,5.54150975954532));
#437=CARTESIAN_POINT('',(40.1465880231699,0.583395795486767,5.5206114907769));
#438=CARTESIAN_POINT('',(40.1338214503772,0.709262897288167,5.50583888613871));
#439=CARTESIAN_POINT('',(40.1022018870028,0.950343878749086,5.46919361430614));
#440=CARTESIAN_POINT('',(40.0838182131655,1.06570311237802,5.44786787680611));
#441=CARTESIAN_POINT('',(40.0411295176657,1.29381096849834,5.3982490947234));
#442=CARTESIAN_POINT('',(40.0168222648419,1.40655858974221,5.36995342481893));
#443=CARTESIAN_POINT('',(39.9356091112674,1.73984674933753,5.2751807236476));
#444=CARTESIAN_POINT('',(39.8703780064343,1.955681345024,5.19877913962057));
#445=CARTESIAN_POINT('',(39.7466819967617,2.30076549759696,5.05275121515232));
#446=CARTESIAN_POINT('',(39.6933328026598,2.43470156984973,4.98950366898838));
#447=CARTESIAN_POINT('',(39.5797013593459,2.6948493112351,4.85393413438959));
#448=CARTESIAN_POINT('',(39.519417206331,2.821058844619,4.78160965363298));
#449=CARTESIAN_POINT('',(39.3293668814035,3.1883592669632,4.55185021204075));
#450=CARTESIAN_POINT('',(39.1907125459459,3.4172894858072,4.38199026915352));
#451=CARTESIAN_POINT('',(38.9573299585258,3.75614165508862,4.08913434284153));
#452=CARTESIAN_POINT('',(38.8672558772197,3.8769998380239,3.97462339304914));
#453=CARTESIAN_POINT('',(38.6834858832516,4.10679298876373,3.7367067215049));
#454=CARTESIAN_POINT('',(38.5897886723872,4.2157236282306,3.61329779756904));
#455=CARTESIAN_POINT('',(38.4015163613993,4.42068084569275,3.35936882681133));
#456=CARTESIAN_POINT('',(38.3069577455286,4.51681890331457,3.22892636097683));
#457=CARTESIAN_POINT('',(38.1653363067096,4.65221359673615,3.02734860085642));
#458=CARTESIAN_POINT('',(38.1181809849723,4.69586329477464,2.95919413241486));
#459=CARTESIAN_POINT('',(38.024207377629,4.78023530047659,2.82086775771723));
#460=CARTESIAN_POINT('',(37.9773891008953,4.82095753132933,2.75069579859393));
#461=CARTESIAN_POINT('',(37.9308783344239,4.86021293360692,2.6795));
#462=B_SPLINE_CURVE_WITH_KNOTS('',3,(#406,#407,#408,#409,#410,#411,#412,#413,#414,#415,#416,
#417,#418,#419,#420,#421,#422,#423,#424,#425,#426,#427,#428,#429,#430,#431,#432,#433,#434,#435,
#436,#437,#438,#439,#440,#441,#442,#443,#444,#445,#446,#447,#448,#449,#450,#451,#452,#453,#454,
#455,#456,#457,#458,#459,#460,#461),.UNSPECIFIED.,.F.,.F.,(4,2,2,2,2,2,2,2,2,2,2,2,2,2,2,2,2,2,
2,2,2,2,2,2,2,2,2,4),(0.,0.294309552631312,0.588613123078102,1.17774797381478,1.77227581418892,
2.36650575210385,3.28677118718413,3.74565786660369,4.20446069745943,4.58459599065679,
4.96465439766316,5.34483298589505,5.72483337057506,6.10646952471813,6.48810596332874,
6.86972329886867,7.25132964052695,7.60716212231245,7.96312883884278,8.67430841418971,
9.14605597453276,9.61793335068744,10.5645286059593,11.1319225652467,11.6995217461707,
12.2617956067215,12.5427445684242,12.8237008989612),.UNSPECIFIED.);
#463=EDGE_CURVE('E265',#96,#57,#462,.T.);
#464=ORIENTED_EDGE('',*,*,#463,.F.);
#465=ORIENTED_EDGE('',*,*,#97,.F.);
#466=CARTESIAN_POINT('',(29.1251216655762,4.86021293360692,2.6795));
#467=CARTESIAN_POINT('',(29.0763989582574,4.81909090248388,2.75408000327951));
#468=CARTESIAN_POINT('',(29.0273401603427,4.77636003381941,2.82753681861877));
#469=CARTESIAN_POINT('',(28.9288672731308,4.68768621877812,2.97223805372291));
#470=CARTESIAN_POINT('',(28.8794531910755,4.64174333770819,3.04348251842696));
#471=CARTESIAN_POINT('',(28.7310616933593,4.49901721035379,3.25407862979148));
#472=CARTESIAN_POINT('',(28.6320235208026,4.39741022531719,3.39015939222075));
#473=CARTESIAN_POINT('',(28.4351438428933,4.18033886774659,3.65453950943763));
#474=CARTESIAN_POINT('',(28.3373215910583,4.0647561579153,3.78275622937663));
#475=CARTESIAN_POINT('',(28.1459362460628,3.82049762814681,4.029307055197));
#476=CARTESIAN_POINT('',(28.0523710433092,3.69182839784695,4.14764608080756));
#477=CARTESIAN_POINT('',(27.8216842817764,3.34676203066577,4.43565665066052));
#478=CARTESIAN_POINT('',(27.6888313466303,3.12096559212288,4.5978682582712));
#479=CARTESIAN_POINT('',(27.5070236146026,2.75981236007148,4.81711655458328));
#480=CARTESIAN_POINT('',(27.4493995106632,2.63586854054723,4.88611027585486));
#481=CARTESIAN_POINT('',(27.3408515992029,2.38067403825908,5.01539772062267));
#482=CARTESIAN_POINT('',(27.2899265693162,2.24942469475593,5.07569303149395));
#483=CARTESIAN_POINT('',(27.2039136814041,2.00333052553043,5.17712379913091));
#484=CARTESIAN_POINT('',(27.1676075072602,1.8895315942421,5.21977180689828));
#485=CARTESIAN_POINT('',(27.1009043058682,1.65782803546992,5.29791803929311));
#486=CARTESIAN_POINT('',(27.0705060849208,1.53992424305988,5.33341770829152));
#487=CARTESIAN_POINT('',(27.0161430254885,1.30057990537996,5.39677782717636));
#488=CARTESIAN_POINT('',(26.992180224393,1.17913825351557,5.42463585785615));
#489=CARTESIAN_POINT('',(26.9511731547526,0.933578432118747,5.47224389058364));
#490=CARTESIAN_POINT('',(26.9341256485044,0.809461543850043,5.49199768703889));
#491=CARTESIAN_POINT('',(26.9072290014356,0.558855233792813,5.52314051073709));
#492=CARTESIAN_POINT('',(26.8974111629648,0.432357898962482,5.53449316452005));
#493=CARTESIAN_POINT('',(26.8853095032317,0.178520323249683,5.5484842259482));
#494=CARTESIAN_POINT('',(26.883025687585,0.0511800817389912,5.55112262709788));
#495=CARTESIAN_POINT('',(26.8860432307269,-0.203283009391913,5.54763517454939));
#496=CARTESIAN_POINT('',(26.89134420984,-0.330405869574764,5.54150975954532));
#497=CARTESIAN_POINT('',(26.9094119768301,-0.583395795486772,5.5206114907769));
#498=CARTESIAN_POINT('',(26.9221785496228,-0.709262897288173,5.50583888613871));
#499=CARTESIAN_POINT('',(26.9537981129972,-0.950343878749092,5.46919361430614));
#500=CARTESIAN_POINT('',(26.9721817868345,-1.06570311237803,5.44786787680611));
#501=CARTESIAN_POINT('',(27.0148704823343,-1.29381096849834,5.39824909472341));
#502=CARTESIAN_POINT('',(27.0391777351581,-1.40655858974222,5.36995342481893));
#503=CARTESIAN_POINT('',(27.1203908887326,-1.73984674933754,5.2751807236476));
#504=CARTESIAN_POINT('',(27.1856219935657,-1.95568134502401,5.19877913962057));
#505=CARTESIAN_POINT('',(27.3093180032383,-2.30076549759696,5.05275121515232));
#506=CARTESIAN_POINT('',(27.3626671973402,-2.43470156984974,4.98950366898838));
#507=CARTESIAN_POINT('',(27.4762986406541,-2.69484931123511,4.85393413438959));
#508=CARTESIAN_POINT('',(27.536582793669,-2.82105884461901,4.78160965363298));
#509=CARTESIAN_POINT('',(27.7266331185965,-3.18835926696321,4.55185021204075));
#510=CARTESIAN_POINT('',(27.8652874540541,-3.41728948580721,4.38199026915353));
#511=CARTESIAN_POINT('',(28.0986700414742,-3.75614165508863,4.08913434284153));
#512=CARTESIAN_POINT('',(28.1887441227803,-3.87699983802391,3.97462339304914));
#513=CARTESIAN_POINT('',(28.3725141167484,-4.10679298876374,3.7367067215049));
#514=CARTESIAN_POINT('',(28.4662113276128,-4.21572362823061,3.61329779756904));
#515=CARTESIAN_POINT('',(28.6544836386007,-4.42068084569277,3.35936882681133));
#516=CARTESIAN_POINT('',(28.7490422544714,-4.51681890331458,3.22892636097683));
#517=CARTESIAN_POINT('',(28.8906636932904,-4.65221359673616,3.02734860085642));
#518=CARTESIAN_POINT('',(28.9378190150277,-4.69586329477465,2.95919413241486));
#519=CARTESIAN_POINT('',(29.031792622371,-4.7802353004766,2.82086775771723));
#520=CARTESIAN_POINT('',(29.0786108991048,-4.82095753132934,2.75069579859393));
#521=CARTESIAN_POINT('',(29.1251216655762,-4.86021293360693,2.6795));
#522=B_SPLINE_CURVE_WITH_KNOTS('',3,(#466,#467,#468,#469,#470,#471,#472,#473,#474,#475,#476,
#477,#478,#479,#480,#481,#482,#483,#484,#485,#486,#487,#488,#489,#490,#491,#492,#493,#494,#495,
#496,#497,#498,#499,#500,#501,#502,#503,#504,#505,#506,#507,#508,#509,#510,#511,#512,#513,#514,
#515,#516,#517,#518,#519,#520,#521),.UNSPECIFIED.,.F.,.F.,(4,2,2,2,2,2,2,2,2,2,2,2,2,2,2,2,2,2,
2,2,2,2,2,2,2,2,2,4),(0.,0.294309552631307,0.588613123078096,1.17774797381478,1.77227581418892,
2.36650575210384,3.28677118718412,3.74565786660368,4.20446069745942,4.58459599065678,
4.96465439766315,5.34483298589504,5.72483337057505,6.10646952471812,6.48810596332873,
6.86972329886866,7.25132964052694,7.60716212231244,7.96312883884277,8.6743084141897,
9.14605597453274,9.61793335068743,10.5645286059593,11.1319225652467,11.6995217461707,
12.2617956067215,12.5427445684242,12.8237008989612),.UNSPECIFIED.);
#523=EDGE_CURVE('E274',#68,#90,#522,.T.);
#524=ORIENTED_EDGE('',*,*,#523,.F.);
#525=ORIENTED_EDGE('',*,*,#69,.F.);
#526=EDGE_LOOP('',(#464,#465,#524,#525));
#527=FACE_BOUND('',#526,.T.);
#528=ADVANCED_FACE('F255',(#405,#527),#394,.F.);
#529=CARTESIAN_POINT('',(33.528,0.,-4.3688));
#530=DIRECTION('',(0.,0.,1.));
#531=DIRECTION('',(1.,0.,0.));
#532=AXIS2_PLACEMENT_3D('',#529,#530,#531);
#533=CONICAL_SURFACE('',#532,5.56260000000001,1.02974425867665);
#534=CARTESIAN_POINT('',(33.528,0.,-7.71114727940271));
#535=VERTEX_POINT('',#534);
#536=VERTEX_LOOP('',#535);
#537=FACE_BOUND('',#536,.T.);
#538=CARTESIAN_POINT('',(38.0487439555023,3.56857461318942,-4.25049));
#539=CARTESIAN_POINT('',(37.9870732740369,3.50636330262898,-4.30271789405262));
#540=CARTESIAN_POINT('',(37.927793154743,3.44155455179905,-4.35480272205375));
#541=CARTESIAN_POINT('',(37.8147987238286,3.30651058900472,-4.45820907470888));
#542=CARTESIAN_POINT('',(37.7610917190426,3.23626845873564,-4.50952952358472));
#543=CARTESIAN_POINT('',(37.6606984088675,3.09101864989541,-4.61028400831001));
#544=CARTESIAN_POINT('',(37.613947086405,3.01606583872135,-4.65973180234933));
#545=CARTESIAN_POINT('',(37.5275186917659,2.86096872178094,-4.75653204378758));
#546=CARTESIAN_POINT('',(37.4878378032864,2.7808272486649,-4.80388561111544));
#547=CARTESIAN_POINT('',(37.4155798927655,2.61513265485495,-4.89607197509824));
#548=CARTESIAN_POINT('',(37.3830571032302,2.52954415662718,-4.94088373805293));
#549=CARTESIAN_POINT('',(37.32532616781,2.35414512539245,-5.02682106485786));
#550=CARTESIAN_POINT('',(37.300119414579,2.26433379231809,-5.0679459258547));
#551=CARTESIAN_POINT('',(37.2563418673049,2.08115803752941,-5.1458810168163));
#552=CARTESIAN_POINT('',(37.2377799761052,1.9877890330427,-5.18268541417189));
#553=CARTESIAN_POINT('',(37.2063059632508,1.79833671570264,-5.25143227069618));
#554=CARTESIAN_POINT('',(37.1933958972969,1.70225242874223,-5.28337295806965));
#555=CARTESIAN_POINT('',(37.1677554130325,1.46919131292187,-5.35378556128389));
#556=CARTESIAN_POINT('',(37.1571605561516,1.33122442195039,-5.38976291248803));
#557=CARTESIAN_POINT('',(37.1415122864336,1.05262087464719,-5.45103233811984));
#558=CARTESIAN_POINT('',(37.1364613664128,0.911983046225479,-5.47631960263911));
#559=CARTESIAN_POINT('',(37.1294196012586,0.628685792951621,-5.51603682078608));
#560=CARTESIAN_POINT('',(37.1274379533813,0.486021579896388,-5.53043407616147));
#561=CARTESIAN_POINT('',(37.125093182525,0.200028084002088,-5.5481441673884));
#562=CARTESIAN_POINT('',(37.1247297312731,0.0566989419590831,-5.5514592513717));
#563=CARTESIAN_POINT('',(37.1252807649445,-0.233620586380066,-5.5469313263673));
#564=CARTESIAN_POINT('',(37.1262297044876,-0.380606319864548,-5.53878738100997));
#565=CARTESIAN_POINT('',(37.1303514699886,-0.67348776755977,-5.51084816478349));
#566=CARTESIAN_POINT('',(37.1335249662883,-0.819383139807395,-5.49104938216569));
#567=CARTESIAN_POINT('',(37.1441832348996,-1.10845549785,-5.44005296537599));
#568=CARTESIAN_POINT('',(37.1516516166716,-1.25164069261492,-5.40889883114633));
#569=CARTESIAN_POINT('',(37.173991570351,-1.53454079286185,-5.33553008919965));
#570=CARTESIAN_POINT('',(37.1888580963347,-1.67425799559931,-5.2933230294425));
#571=CARTESIAN_POINT('',(37.2230332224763,-1.90453819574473,-5.21381382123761));
#572=CARTESIAN_POINT('',(37.2393892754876,-1.99649821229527,-5.1792779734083));
#573=CARTESIAN_POINT('',(37.2781834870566,-2.17734763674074,-5.10588468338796));
#574=CARTESIAN_POINT('',(37.3006194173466,-2.26623815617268,-5.06702882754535));
#575=CARTESIAN_POINT('',(37.3523080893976,-2.44022162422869,-4.98557264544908));
#576=CARTESIAN_POINT('',(37.3815589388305,-2.52531561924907,-4.94297336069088));
#577=CARTESIAN_POINT('',(37.4471933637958,-2.69105186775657,-4.85473403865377));
#578=CARTESIAN_POINT('',(37.4835759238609,-2.77169475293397,-4.80909443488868));
#579=CARTESIAN_POINT('',(37.5577947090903,-2.91721547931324,-4.72201343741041));
#580=CARTESIAN_POINT('',(37.5947328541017,-2.98273052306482,-4.68086521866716));
#581=CARTESIAN_POINT('',(37.6734702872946,-3.10995290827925,-4.59732257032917));
#582=CARTESIAN_POINT('',(37.7152706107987,-3.17165943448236,-4.554927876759));
#583=CARTESIAN_POINT('',(37.803448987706,-3.29146120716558,-4.46913061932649));
#584=CARTESIAN_POINT('',(37.8498450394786,-3.34954067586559,-4.42572464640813));
#585=CARTESIAN_POINT('',(37.9465126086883,-3.46187931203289,-4.33841352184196));
#586=CARTESIAN_POINT('',(37.9967810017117,-3.51614149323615,-4.29450879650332));
#587=CARTESIAN_POINT('',(38.0487439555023,-3.56857461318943,-4.25049));
#588=B_SPLINE_CURVE_WITH_KNOTS('',3,(#538,#539,#540,#541,#542,#543,#544,#545,#546,#547,#548,
#549,#550,#551,#552,#553,#554,#555,#556,#557,#558,#559,#560,#561,#562,#563,#564,#565,#566,#567,
#568,#569,#570,#571,#572,#573,#574,#575,#576,#577,#578,#579,#580,#581,#582,#583,#584,#585,#586,
#587),.UNSPECIFIED.,.F.,.F.,(4,2,2,2,2,2,2,2,2,2,2,2,2,2,2,2,2,2,2,2,2,2,2,2,4),(0.,
0.305998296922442,0.61239284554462,0.915714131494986,1.21887119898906,1.52425155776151,
1.82969000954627,2.13553617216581,2.44149348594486,2.86977815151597,3.29825531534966,
3.72801396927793,4.15768543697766,4.59885384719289,5.04015525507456,5.47978359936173,
5.91911250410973,6.21758087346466,6.51594000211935,6.81421638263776,7.1124503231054,
7.36940866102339,7.62642181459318,7.88448461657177,8.14234133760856),.UNSPECIFIED.);
#589=EDGE_CURVE('E11',#184,#316,#588,.T.);
#590=ORIENTED_EDGE('',*,*,#589,.F.);
#591=ORIENTED_EDGE('',*,*,#185,.T.);
#592=CARTESIAN_POINT('',(29.0072560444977,-3.56857461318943,-4.25049));
#593=CARTESIAN_POINT('',(29.0689267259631,-3.50636330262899,-4.30271789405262));
#594=CARTESIAN_POINT('',(29.1282068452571,-3.44155455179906,-4.35480272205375));
#595=CARTESIAN_POINT('',(29.2412012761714,-3.30651058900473,-4.45820907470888));
#596=CARTESIAN_POINT('',(29.2949082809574,-3.23626845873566,-4.50952952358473));
#597=CARTESIAN_POINT('',(29.3953015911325,-3.09101864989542,-4.61028400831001));
#598=CARTESIAN_POINT('',(29.442052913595,-3.01606583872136,-4.65973180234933));
#599=CARTESIAN_POINT('',(29.5284813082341,-2.86096872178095,-4.75653204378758));
#600=CARTESIAN_POINT('',(29.5681621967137,-2.78082724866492,-4.80388561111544));
#601=CARTESIAN_POINT('',(29.6404201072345,-2.61513265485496,-4.89607197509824));
#602=CARTESIAN_POINT('',(29.6729428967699,-2.52954415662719,-4.94088373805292));
#603=CARTESIAN_POINT('',(29.73067383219,-2.35414512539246,-5.02682106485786));
#604=CARTESIAN_POINT('',(29.755880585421,-2.26433379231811,-5.06794592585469));
#605=CARTESIAN_POINT('',(29.7996581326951,-2.08115803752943,-5.14588101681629));
#606=CARTESIAN_POINT('',(29.8182200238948,-1.98778903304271,-5.18268541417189));
#607=CARTESIAN_POINT('',(29.8496940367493,-1.79833671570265,-5.25143227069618));
#608=CARTESIAN_POINT('',(29.8626041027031,-1.70225242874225,-5.28337295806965));
#609=CARTESIAN_POINT('',(29.8882445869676,-1.46919131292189,-5.35378556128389));
#610=CARTESIAN_POINT('',(29.8988394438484,-1.33122442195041,-5.38976291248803));
#611=CARTESIAN_POINT('',(29.9144877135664,-1.05262087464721,-5.45103233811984));
#612=CARTESIAN_POINT('',(29.9195386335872,-0.911983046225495,-5.47631960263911));
#613=CARTESIAN_POINT('',(29.9265803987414,-0.628685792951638,-5.51603682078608));
#614=CARTESIAN_POINT('',(29.9285620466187,-0.486021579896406,-5.53043407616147));
#615=CARTESIAN_POINT('',(29.930906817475,-0.200028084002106,-5.5481441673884));
#616=CARTESIAN_POINT('',(29.9312702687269,-0.0566989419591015,-5.5514592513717));
#617=CARTESIAN_POINT('',(29.9307192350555,0.233620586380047,-5.5469313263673));
#618=CARTESIAN_POINT('',(29.9297702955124,0.380606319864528,-5.53878738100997));
#619=CARTESIAN_POINT('',(29.9256485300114,0.67348776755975,-5.51084816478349));
#620=CARTESIAN_POINT('',(29.9224750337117,0.819383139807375,-5.49104938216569));
#621=CARTESIAN_POINT('',(29.9118167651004,1.10845549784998,-5.44005296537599));
#622=CARTESIAN_POINT('',(29.9043483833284,1.25164069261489,-5.40889883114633));
#623=CARTESIAN_POINT('',(29.882008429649,1.53454079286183,-5.33553008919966));
#624=CARTESIAN_POINT('',(29.8671419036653,1.67425799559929,-5.2933230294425));
#625=CARTESIAN_POINT('',(29.8329667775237,1.9045381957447,-5.21381382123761));
#626=CARTESIAN_POINT('',(29.8166107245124,1.99649821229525,-5.1792779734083));
#627=CARTESIAN_POINT('',(29.7778165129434,2.17734763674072,-5.10588468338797));
#628=CARTESIAN_POINT('',(29.7553805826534,2.26623815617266,-5.06702882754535));
#629=CARTESIAN_POINT('',(29.7036919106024,2.44022162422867,-4.98557264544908));
#630=CARTESIAN_POINT('',(29.6744410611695,2.52531561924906,-4.94297336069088));
#631=CARTESIAN_POINT('',(29.6088066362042,2.69105186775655,-4.85473403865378));
#632=CARTESIAN_POINT('',(29.5724240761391,2.77169475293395,-4.80909443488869));
#633=CARTESIAN_POINT('',(29.4982052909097,2.91721547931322,-4.72201343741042));
#634=CARTESIAN_POINT('',(29.4612671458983,2.98273052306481,-4.68086521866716));
#635=CARTESIAN_POINT('',(29.3825297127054,3.10995290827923,-4.59732257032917));
#636=CARTESIAN_POINT('',(29.3407293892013,3.17165943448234,-4.554927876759));
#637=CARTESIAN_POINT('',(29.252551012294,3.29146120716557,-4.46913061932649));
#638=CARTESIAN_POINT('',(29.2061549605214,3.34954067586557,-4.42572464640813));
#639=CARTESIAN_POINT('',(29.1094873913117,3.46187931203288,-4.33841352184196));
#640=CARTESIAN_POINT('',(29.0592189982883,3.51614149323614,-4.29450879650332));
#641=CARTESIAN_POINT('',(29.0072560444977,3.56857461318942,-4.25049));
#642=B_SPLINE_CURVE_WITH_KNOTS('',3,(#592,#593,#594,#595,#596,#597,#598,#599,#600,#601,#602,
#603,#604,#605,#606,#607,#608,#609,#610,#611,#612,#613,#614,#615,#616,#617,#618,#619,#620,#621,
#622,#623,#624,#625,#626,#627,#628,#629,#630,#631,#632,#633,#634,#635,#636,#637,#638,#639,#640,
#641),.UNSPECIFIED.,.F.,.F.,(4,2,2,2,2,2,2,2,2,2,2,2,2,2,2,2,2,2,2,2,2,2,2,2,4),(0.,
0.305998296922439,0.61239284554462,0.915714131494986,1.21887119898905,1.5242515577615,
1.82969000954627,2.13553617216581,2.44149348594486,2.86977815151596,3.29825531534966,
3.72801396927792,4.15768543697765,4.59885384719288,5.04015525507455,5.47978359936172,
5.91911250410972,6.21758087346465,6.51594000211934,6.81421638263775,7.1124503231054,
7.36940866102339,7.62642181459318,7.88448461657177,8.14234133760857),.UNSPECIFIED.);
#643=EDGE_CURVE('E44',#320,#175,#642,.T.);
#644=ORIENTED_EDGE('',*,*,#643,.F.);
#645=ORIENTED_EDGE('',*,*,#321,.T.);
#646=EDGE_LOOP('',(#590,#591,#644,#645));
#647=FACE_BOUND('',#646,.T.);
#648=ADVANCED_FACE('F167',(#537,#647),#533,.F.);
#649=CARTESIAN_POINT('',(52.9844,0.,0.));
#650=DIRECTION('',(1.,0.,0.));
#651=DIRECTION('',(0.,0.,-1.));
#652=AXIS2_PLACEMENT_3D('',#649,#650,#651);
#653=PLANE('',#652);
#654=CARTESIAN_POINT('',(52.9844,0.,0.));
#655=DIRECTION('',(1.,0.,0.));
#656=DIRECTION('',(0.,0.,-1.));
#657=AXIS2_PLACEMENT_3D('',#654,#655,#656);
#658=CIRCLE('',#657,11.1125);
#659=CARTESIAN_POINT('',(52.9844,0.,11.1125));
#660=VERTEX_POINT('',#659);
#661=EDGE_CURVE('E179',#660,#660,#658,.T.);
#662=ORIENTED_EDGE('',*,*,#661,.T.);
#663=EDGE_LOOP('',(#662));
#664=FACE_BOUND('',#663,.T.);
#665=CARTESIAN_POINT('',(52.9844,0.,0.));
#666=DIRECTION('',(-1.,0.,0.));
#667=DIRECTION('',(0.,0.,1.));
#668=AXIS2_PLACEMENT_3D('',#665,#666,#667);
#669=CIRCLE('',#668,6.73100000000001);
#670=CARTESIAN_POINT('',(52.9844,0.,6.73100000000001));
#671=VERTEX_POINT('',#670);
#672=EDGE_CURVE('E511',#671,#671,#669,.T.);
#673=ORIENTED_EDGE('',*,*,#672,.T.);
#674=EDGE_LOOP('',(#673));
#675=FACE_BOUND('',#674,.T.);
#676=ADVANCED_FACE('F337',(#664,#675),#653,.T.);
#677=CARTESIAN_POINT('',(16.4084,0.,0.));
#678=DIRECTION('',(1.,0.,0.));
#679=DIRECTION('',(0.,0.,-1.));
#680=AXIS2_PLACEMENT_3D('',#677,#678,#679);
#681=CONICAL_SURFACE('',#680,3.17499999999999,1.02974425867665);
#682=CARTESIAN_POINT('',(16.1699334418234,0.,0.));
#683=DIRECTION('',(1.,0.,0.));
#684=DIRECTION('',(0.,0.,-1.));
#685=AXIS2_PLACEMENT_3D('',#682,#683,#684);
#686=CIRCLE('',#685,2.77812499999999);
#687=CARTESIAN_POINT('',(16.1699334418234,0.,-2.77812499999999));
#688=VERTEX_POINT('',#687);
#689=EDGE_CURVE('E168',#688,#688,#686,.F.);
#690=ORIENTED_EDGE('',*,*,#689,.T.);
#691=EDGE_LOOP('',(#690));
#692=FACE_BOUND('',#691,.T.);
#693=ORIENTED_EDGE('',*,*,#31,.T.);
#694=EDGE_LOOP('',(#693));
#695=FACE_BOUND('',#694,.T.);
#696=ADVANCED_FACE('F343',(#692,#695),#681,.F.);
#697=CARTESIAN_POINT('',(52.9844,0.,0.));
#698=DIRECTION('',(1.,0.,0.));
#699=DIRECTION('',(0.,0.,-1.));
#700=AXIS2_PLACEMENT_3D('',#697,#698,#699);
#701=CYLINDRICAL_SURFACE('',#700,2.77812499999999);
#702=CARTESIAN_POINT('',(14.6448051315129,0.73366086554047,-2.67949999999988));
#703=CARTESIAN_POINT('',(14.6532420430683,0.663922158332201,-2.6986051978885));
#704=CARTESIAN_POINT('',(14.660541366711,0.593299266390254,-2.71500496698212));
#705=CARTESIAN_POINT('',(14.6727345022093,0.450769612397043,-2.74226854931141));
#706=CARTESIAN_POINT('',(14.6776276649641,0.378862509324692,-2.75313086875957));
#707=CARTESIAN_POINT('',(14.6847860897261,0.236030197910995,-2.76899046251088));
#708=CARTESIAN_POINT('',(14.6871118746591,0.16512312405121,-2.77412284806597));
#709=CARTESIAN_POINT('',(14.6892938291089,0.0231210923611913,-2.77893740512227));
#710=CARTESIAN_POINT('',(14.6891507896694,-0.0479737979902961,-2.77862132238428));
#711=CARTESIAN_POINT('',(14.6857660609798,-0.222097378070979,-2.77115355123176));
#712=CARTESIAN_POINT('',(14.6811493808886,-0.324995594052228,-2.76096875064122));
#713=CARTESIAN_POINT('',(14.670421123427,-0.478609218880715,-2.73709192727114));
#714=CARTESIAN_POINT('',(14.6661549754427,-0.530152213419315,-2.72757381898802));
#715=CARTESIAN_POINT('',(14.6563898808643,-0.632497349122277,-2.70567199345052));
#716=CARTESIAN_POINT('',(14.6508911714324,-0.683299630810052,-2.6932888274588));
#717=CARTESIAN_POINT('',(14.6448051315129,-0.733660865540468,-2.67949999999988));
#718=B_SPLINE_CURVE_WITH_KNOTS('',3,(#702,#703,#704,#705,#706,#707,#708,#709,#710,#711,#712,
#713,#714,#715,#716,#717),.UNSPECIFIED.,.F.,.F.,(4,2,2,2,2,2,2,4),(0.,0.218340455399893,
0.436739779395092,0.649872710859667,0.862937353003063,1.17256731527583,1.33024905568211,
1.48790048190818),.UNSPECIFIED.);
#719=CARTESIAN_POINT('',(14.6448933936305,0.732930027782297,-2.6797));
#720=VERTEX_POINT('',#719);
#721=CARTESIAN_POINT('',(14.6448933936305,-0.732930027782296,-2.6797));
#722=VERTEX_POINT('',#721);
#723=EDGE_CURVE('E459',#720,#722,#718,.T.);
#724=ORIENTED_EDGE('',*,*,#723,.T.);
#725=DIRECTION('',(1.,0.,0.));
#726=VECTOR('',#725,1.);
#727=CARTESIAN_POINT('',(52.9844,-0.732930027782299,-2.6797));
#728=LINE('',#727,#726);
#729=CARTESIAN_POINT('',(13.6421030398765,-0.732930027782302,-2.6797));
#730=VERTEX_POINT('',#729);
#731=EDGE_CURVE('E156',#722,#730,#728,.F.);
#732=ORIENTED_EDGE('',*,*,#731,.T.);
#733=CARTESIAN_POINT('',(13.6421030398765,0.732930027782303,2.6797));
#734=CARTESIAN_POINT('',(13.6320733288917,0.808474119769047,2.65904656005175));
#735=CARTESIAN_POINT('',(13.6205846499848,0.882937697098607,2.63523828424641));
#736=CARTESIAN_POINT('',(13.5950642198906,1.02917415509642,2.58163265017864));
#737=CARTESIAN_POINT('',(13.5810341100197,1.10094873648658,2.55183915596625));
#738=CARTESIAN_POINT('',(13.550848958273,1.24111072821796,2.48667963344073));
#739=CARTESIAN_POINT('',(13.5347021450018,1.30950991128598,2.45133508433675));
#740=CARTESIAN_POINT('',(13.5006662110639,1.44281508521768,2.37532226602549));
#741=CARTESIAN_POINT('',(13.4827768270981,1.50772054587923,2.33465319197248));
#742=CARTESIAN_POINT('',(13.4272371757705,1.69638292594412,2.20532244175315));
#743=CARTESIAN_POINT('',(13.3876174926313,1.81452015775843,2.1091335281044));
#744=CARTESIAN_POINT('',(13.3069399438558,2.0334135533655,1.89902320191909));
#745=CARTESIAN_POINT('',(13.2658800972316,2.13414454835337,1.78507655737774));
#746=CARTESIAN_POINT('',(13.1840827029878,2.32155196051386,1.53437597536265));
#747=CARTESIAN_POINT('',(13.1435109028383,2.40702948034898,1.39666626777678));
#748=CARTESIAN_POINT('',(13.0706320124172,2.5533600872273,1.10662148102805));
#749=CARTESIAN_POINT('',(13.0383182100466,2.61423319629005,0.954298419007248));
#750=CARTESIAN_POINT('',(13.0004396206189,2.68374389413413,0.722225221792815));
#751=CARTESIAN_POINT('',(12.9897385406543,2.70302625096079,0.646363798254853));
#752=CARTESIAN_POINT('',(12.9717295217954,2.73516873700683,0.492912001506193));
#753=CARTESIAN_POINT('',(12.9644197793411,2.74803228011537,0.415322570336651));
#754=CARTESIAN_POINT('',(12.9535175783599,2.76713240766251,0.259119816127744));
#755=CARTESIAN_POINT('',(12.949922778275,2.77337316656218,0.180507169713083));
#756=CARTESIAN_POINT('',(12.9465942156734,2.77914942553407,0.0229797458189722));
#757=CARTESIAN_POINT('',(12.9468600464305,2.77868563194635,-0.0559349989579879));
#758=CARTESIAN_POINT('',(12.9529350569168,2.76814687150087,-0.272776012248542));
#759=CARTESIAN_POINT('',(12.9627731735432,2.75108809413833,-0.410328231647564));
#760=CARTESIAN_POINT('',(12.9930894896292,2.69709869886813,-0.680164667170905));
#761=CARTESIAN_POINT('',(13.0135708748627,2.66016213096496,-0.812447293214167));
#762=CARTESIAN_POINT('',(13.0630210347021,2.56727028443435,-1.07060026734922));
#763=CARTESIAN_POINT('',(13.0921057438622,2.51105342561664,-1.1963534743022));
#764=CARTESIAN_POINT('',(13.1555757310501,2.38142818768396,-1.43718743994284));
#765=CARTESIAN_POINT('',(13.1899632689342,2.30801247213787,-1.55226361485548));
#766=CARTESIAN_POINT('',(13.2654001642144,2.13531746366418,-1.78375547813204));
#767=CARTESIAN_POINT('',(13.3067434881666,2.03394680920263,-1.89852011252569));
#768=CARTESIAN_POINT('',(13.3880210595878,1.81342499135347,-2.11017597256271));
#769=CARTESIAN_POINT('',(13.4279545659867,1.69426464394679,-2.20705790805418));
#770=CARTESIAN_POINT('',(13.5045055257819,1.43356564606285,-2.38518092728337));
#771=CARTESIAN_POINT('',(13.5408298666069,1.29116904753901,-2.46530311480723));
#772=CARTESIAN_POINT('',(13.6034245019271,0.992685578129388,-2.59986442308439));
#773=CARTESIAN_POINT('',(13.6297023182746,0.836609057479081,-2.65432276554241));
#774=CARTESIAN_POINT('',(13.6674624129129,0.528277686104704,-2.73169303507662));
#775=CARTESIAN_POINT('',(13.6799439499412,0.376684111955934,-2.75674520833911));
#776=CARTESIAN_POINT('',(13.6922465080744,0.0709594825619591,-2.78144306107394));
#777=CARTESIAN_POINT('',(13.6920741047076,-0.0831702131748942,-2.78110193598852));
#778=CARTESIAN_POINT('',(13.6796429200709,-0.376237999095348,-2.75613637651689));
#779=CARTESIAN_POINT('',(13.6683671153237,-0.515393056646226,-2.73348685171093));
#780=CARTESIAN_POINT('',(13.6362615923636,-0.787633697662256,-2.66781256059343));
#781=CARTESIAN_POINT('',(13.6154309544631,-0.920718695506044,-2.62478583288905));
#782=CARTESIAN_POINT('',(13.565508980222,-1.18065520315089,-2.51876862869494));
#783=CARTESIAN_POINT('',(13.5362388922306,-1.30729332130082,-2.45534230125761));
#784=CARTESIAN_POINT('',(13.4721791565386,-1.54850449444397,-2.31082312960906));
#785=CARTESIAN_POINT('',(13.437387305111,-1.66307270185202,-2.22972322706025));
#786=CARTESIAN_POINT('',(13.361629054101,-1.88868761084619,-2.04310903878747));
#787=CARTESIAN_POINT('',(13.3203910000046,-1.9983183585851,-1.93599084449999));
#788=CARTESIAN_POINT('',(13.2387531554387,-2.19873961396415,-1.70497310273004));
#789=CARTESIAN_POINT('',(13.1983539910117,-2.28951647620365,-1.5810615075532));
#790=CARTESIAN_POINT('',(13.1207255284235,-2.45437750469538,-1.3115933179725));
#791=CARTESIAN_POINT('',(13.0837874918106,-2.52728752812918,-1.1652267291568));
#792=CARTESIAN_POINT('',(13.0210388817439,-2.64675286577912,-0.859920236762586));
#793=CARTESIAN_POINT('',(12.9952150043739,-2.6933397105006,-0.700995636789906));
#794=CARTESIAN_POINT('',(12.9607224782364,-2.75471460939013,-0.390260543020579));
#795=CARTESIAN_POINT('',(12.9507222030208,-2.77198126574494,-0.239091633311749));
#796=CARTESIAN_POINT('',(12.9452324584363,-2.78151755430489,0.0642632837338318));
#797=CARTESIAN_POINT('',(12.9497352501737,-2.77380051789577,0.216448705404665));
#798=CARTESIAN_POINT('',(12.9713084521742,-2.73592012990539,0.501266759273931));
#799=CARTESIAN_POINT('',(12.9870663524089,-2.70809767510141,0.634324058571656));
#800=CARTESIAN_POINT('',(13.0276721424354,-2.63391487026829,0.893686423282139));
#801=CARTESIAN_POINT('',(13.0525225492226,-2.58754938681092,1.01998960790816));
#802=CARTESIAN_POINT('',(13.1102919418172,-2.47457593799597,1.27061403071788));
#803=CARTESIAN_POINT('',(13.1436014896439,-2.40693212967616,1.39437531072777));
#804=CARTESIAN_POINT('',(13.2140129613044,-2.25434028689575,1.6296044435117));
#805=CARTESIAN_POINT('',(13.2511180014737,-2.16937797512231,1.74106203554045));
#806=CARTESIAN_POINT('',(13.3304425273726,-1.97224319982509,1.9628802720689));
#807=CARTESIAN_POINT('',(13.3727251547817,-1.85800227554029,2.07138745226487));
#808=CARTESIAN_POINT('',(13.4534441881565,-1.61209789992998,2.26800409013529));
#809=CARTESIAN_POINT('',(13.4918853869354,-1.48045664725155,2.35613915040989));
#810=CARTESIAN_POINT('',(13.5500983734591,-1.24619913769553,2.4853211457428));
#811=CARTESIAN_POINT('',(13.5719445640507,-1.14742518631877,2.53246753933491));
#812=CARTESIAN_POINT('',(13.6108733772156,-0.944159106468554,2.61507452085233));
#813=CARTESIAN_POINT('',(13.6279532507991,-0.839663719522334,2.65052836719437));
#814=CARTESIAN_POINT('',(13.6421030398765,-0.732930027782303,2.6797));
#815=B_SPLINE_CURVE_WITH_KNOTS('',3,(#733,#734,#735,#736,#737,#738,#739,#740,#741,#742,#743,
#744,#745,#746,#747,#748,#749,#750,#751,#752,#753,#754,#755,#756,#757,#758,#759,#760,#761,#762,
#763,#764,#765,#766,#767,#768,#769,#770,#771,#772,#773,#774,#775,#776,#777,#778,#779,#780,#781,
#782,#783,#784,#785,#786,#787,#788,#789,#790,#791,#792,#793,#794,#795,#796,#797,#798,#799,#800,
#801,#802,#803,#804,#805,#806,#807,#808,#809,#810,#811,#812,#813,#814),.UNSPECIFIED.,.F.,.F.,(4,
2,2,2,2,2,2,2,2,2,2,2,2,2,2,2,2,2,2,2,2,2,2,2,2,2,2,2,2,2,2,2,2,2,2,2,2,2,2,2,4),(0.,
0.236750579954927,0.473348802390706,0.70905311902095,0.944793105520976,1.41482203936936,
1.88552503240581,2.38434387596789,2.88275598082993,3.11947061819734,3.35605922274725,
3.59249861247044,3.82891309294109,4.24360159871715,4.65841430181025,5.07909339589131,
5.49995226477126,5.97373095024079,6.44775507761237,6.94722711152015,7.44632445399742,
7.90625484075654,8.36594622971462,8.78829451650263,9.21068346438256,9.64277434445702,
10.075038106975,10.549170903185,11.0236456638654,11.5238857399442,12.0235253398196,
12.4783239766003,12.9328799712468,13.3416186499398,13.7504705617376,14.1835260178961,
14.6169399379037,15.1041525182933,15.5907494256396,15.9247650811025,16.2589729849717),.UNSPECIFIED.);
#816=CARTESIAN_POINT('',(13.6421030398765,-0.732930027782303,2.6797));
#817=VERTEX_POINT('',#816);
#818=EDGE_CURVE('E228',#730,#817,#815,.T.);
#819=ORIENTED_EDGE('',*,*,#818,.T.);
#820=DIRECTION('',(1.,0.,0.));
#821=VECTOR('',#820,1.);
#822=CARTESIAN_POINT('',(52.9844,-0.732930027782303,2.6797));
#823=LINE('',#822,#821);
#824=CARTESIAN_POINT('',(14.6448933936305,-0.732930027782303,2.6797));
#825=VERTEX_POINT('',#824);
#826=EDGE_CURVE('E239',#817,#825,#823,.T.);
#827=ORIENTED_EDGE('',*,*,#826,.T.);
#828=CARTESIAN_POINT('',(14.6448051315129,-0.733660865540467,2.67949999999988));
#829=CARTESIAN_POINT('',(14.6532420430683,-0.663922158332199,2.6986051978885));
#830=CARTESIAN_POINT('',(14.660541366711,-0.593299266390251,2.71500496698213));
#831=CARTESIAN_POINT('',(14.6727345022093,-0.45076961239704,2.74226854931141));
#832=CARTESIAN_POINT('',(14.6776276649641,-0.37886250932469,2.75313086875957));
#833=CARTESIAN_POINT('',(14.6847860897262,-0.236030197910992,2.76899046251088));
#834=CARTESIAN_POINT('',(14.6871118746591,-0.165123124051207,2.77412284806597));
#835=CARTESIAN_POINT('',(14.6892938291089,-0.0231210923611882,2.77893740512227));
#836=CARTESIAN_POINT('',(14.6891507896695,0.0479737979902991,2.77862132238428));
#837=CARTESIAN_POINT('',(14.6857660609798,0.222097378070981,2.77115355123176));
#838=CARTESIAN_POINT('',(14.6811493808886,0.324995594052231,2.76096875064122));
#839=CARTESIAN_POINT('',(14.670421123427,0.478609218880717,2.73709192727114));
#840=CARTESIAN_POINT('',(14.6661549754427,0.530152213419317,2.72757381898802));
#841=CARTESIAN_POINT('',(14.6563898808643,0.632497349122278,2.70567199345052));
#842=CARTESIAN_POINT('',(14.6508911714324,0.683299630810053,2.6932888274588));
#843=CARTESIAN_POINT('',(14.6448051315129,0.733660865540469,2.67949999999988));
#844=B_SPLINE_CURVE_WITH_KNOTS('',3,(#828,#829,#830,#831,#832,#833,#834,#835,#836,#837,#838,
#839,#840,#841,#842,#843),.UNSPECIFIED.,.F.,.F.,(4,2,2,2,2,2,2,4),(0.,0.218340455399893,
0.436739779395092,0.649872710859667,0.862937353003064,1.17256731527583,1.3302490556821,
1.48790048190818),.UNSPECIFIED.);
#845=CARTESIAN_POINT('',(14.6448933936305,0.732930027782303,2.6797));
#846=VERTEX_POINT('',#845);
#847=EDGE_CURVE('E460',#825,#846,#844,.T.);
#848=ORIENTED_EDGE('',*,*,#847,.T.);
#849=DIRECTION('',(1.,0.,0.));
#850=VECTOR('',#849,1.);
#851=CARTESIAN_POINT('',(52.9844,0.732930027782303,2.6797));
#852=LINE('',#851,#850);
#853=CARTESIAN_POINT('',(13.6421030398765,0.732930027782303,2.6797));
#854=VERTEX_POINT('',#853);
#855=EDGE_CURVE('E468',#846,#854,#852,.F.);
#856=ORIENTED_EDGE('',*,*,#855,.T.);
#857=CARTESIAN_POINT('',(13.6421030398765,0.732930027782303,-2.6797));
#858=VERTEX_POINT('',#857);
#859=EDGE_CURVE('E230',#854,#858,#815,.T.);
#860=ORIENTED_EDGE('',*,*,#859,.T.);
#861=DIRECTION('',(1.,0.,0.));
#862=VECTOR('',#861,1.);
#863=CARTESIAN_POINT('',(52.9844,0.7329300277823,-2.6797));
#864=LINE('',#863,#862);
#865=EDGE_CURVE('E696',#858,#720,#864,.T.);
#866=ORIENTED_EDGE('',*,*,#865,.T.);
#867=EDGE_LOOP('',(#724,#732,#819,#827,#848,#856,#860,#866));
#868=FACE_BOUND('',#867,.T.);
#869=ORIENTED_EDGE('',*,*,#689,.F.);
#870=EDGE_LOOP('',(#869));
#871=FACE_BOUND('',#870,.T.);
#872=ADVANCED_FACE('F241',(#868,#871),#701,.F.);
#873=CARTESIAN_POINT('',(42.0624,-14.6646968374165,0.));
#874=DIRECTION('',(0.,0.866025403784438,0.500000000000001));
#875=DIRECTION('',(0.,-0.500000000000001,0.866025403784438));
#876=AXIS2_PLACEMENT_3D('',#873,#874,#875);
#877=PLANE('',#876);
#878=DIRECTION('',(0.,0.500000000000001,-0.866025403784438));
#879=VECTOR('',#878,1.);
#880=CARTESIAN_POINT('',(0.,-14.6646968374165,0.));
#881=LINE('',#880,#879);
#882=CARTESIAN_POINT('',(0.,-14.6646968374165,0.));
#883=VERTEX_POINT('',#882);
#884=CARTESIAN_POINT('',(0.,-7.33234841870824,-12.7));
#885=VERTEX_POINT('',#884);
#886=EDGE_CURVE('E205',#883,#885,#881,.T.);
#887=ORIENTED_EDGE('',*,*,#886,.T.);
#888=DIRECTION('',(-1.,0.,0.));
#889=VECTOR('',#888,1.);
#890=CARTESIAN_POINT('',(42.0624,-7.33234841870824,-12.7));
#891=LINE('',#890,#889);
#892=CARTESIAN_POINT('',(42.0624,-7.33234841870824,-12.7));
#893=VERTEX_POINT('',#892);
#894=EDGE_CURVE('E220',#893,#885,#891,.T.);
#895=ORIENTED_EDGE('',*,*,#894,.F.);
#896=DIRECTION('',(0.,0.500000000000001,-0.866025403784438));
#897=VECTOR('',#896,1.);
#898=CARTESIAN_POINT('',(42.0624,-14.6646968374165,0.));
#899=LINE('',#898,#897);
#900=CARTESIAN_POINT('',(42.0624,-14.6646968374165,0.));
#901=VERTEX_POINT('',#900);
#902=EDGE_CURVE('E192',#901,#893,#899,.T.);
#903=ORIENTED_EDGE('',*,*,#902,.F.);
#904=DIRECTION('',(-1.,0.,0.));
#905=VECTOR('',#904,1.);
#906=CARTESIAN_POINT('',(42.0624,-14.6646968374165,0.));
#907=LINE('',#906,#905);
#908=EDGE_CURVE('E223',#901,#883,#907,.T.);
#909=ORIENTED_EDGE('',*,*,#908,.T.);
#910=EDGE_LOOP('',(#887,#895,#903,#909));
#911=FACE_BOUND('',#910,.T.);
#912=ADVANCED_FACE('F382',(#911),#877,.F.);
#913=CARTESIAN_POINT('',(42.0624,-7.33234841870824,-12.7));
#914=DIRECTION('',(0.,0.,1.));
#915=DIRECTION('',(0.,-1.,0.));
#916=AXIS2_PLACEMENT_3D('',#913,#914,#915);
#917=PLANE('',#916);
#918=CARTESIAN_POINT('',(8.128,0.,-12.7));
#919=DIRECTION('',(0.,0.,-1.));
#920=DIRECTION('',(0.,1.,0.));
#921=AXIS2_PLACEMENT_3D('',#918,#919,#920);
#922=CIRCLE('',#921,6.858);
#923=CARTESIAN_POINT('',(8.128,6.85800000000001,-12.7));
#924=VERTEX_POINT('',#923);
#925=EDGE_CURVE('E446',#924,#924,#922,.T.);
#926=ORIENTED_EDGE('',*,*,#925,.F.);
#927=EDGE_LOOP('',(#926));
#928=FACE_BOUND('',#927,.T.);
#929=DIRECTION('',(0.,1.,0.));
#930=VECTOR('',#929,1.);
#931=CARTESIAN_POINT('',(0.,-7.33234841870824,-12.7));
#932=LINE('',#931,#930);
#933=CARTESIAN_POINT('',(0.,7.33234841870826,-12.7));
#934=VERTEX_POINT('',#933);
#935=EDGE_CURVE('E207',#885,#934,#932,.T.);
#936=ORIENTED_EDGE('',*,*,#935,.T.);
#937=DIRECTION('',(-1.,0.,0.));
#938=VECTOR('',#937,1.);
#939=CARTESIAN_POINT('',(42.0624,7.33234841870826,-12.7));
#940=LINE('',#939,#938);
#941=CARTESIAN_POINT('',(42.0624,7.33234841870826,-12.7));
#942=VERTEX_POINT('',#941);
#943=EDGE_CURVE('E217',#942,#934,#940,.T.);
#944=ORIENTED_EDGE('',*,*,#943,.F.);
#945=DIRECTION('',(0.,1.,0.));
#946=VECTOR('',#945,1.);
#947=CARTESIAN_POINT('',(42.0624,-7.33234841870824,-12.7));
#948=LINE('',#947,#946);
#949=EDGE_CURVE('E194',#893,#942,#948,.T.);
#950=ORIENTED_EDGE('',*,*,#949,.F.);
#951=ORIENTED_EDGE('',*,*,#894,.T.);
#952=EDGE_LOOP('',(#936,#944,#950,#951));
#953=FACE_BOUND('',#952,.T.);
#954=ADVANCED_FACE('F378',(#928,#953),#917,.F.);
#955=CARTESIAN_POINT('',(42.0624,7.33234841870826,-12.7));
#956=DIRECTION('',(0.,-0.866025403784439,0.5));
#957=DIRECTION('',(0.,-0.5,-0.866025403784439));
#958=AXIS2_PLACEMENT_3D('',#955,#956,#957);
#959=PLANE('',#958);
#960=DIRECTION('',(0.,0.5,0.866025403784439));
#961=VECTOR('',#960,1.);
#962=CARTESIAN_POINT('',(0.,7.33234841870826,-12.7));
#963=LINE('',#962,#961);
#964=CARTESIAN_POINT('',(0.,14.6646968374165,0.));
#965=VERTEX_POINT('',#964);
#966=EDGE_CURVE('E209',#934,#965,#963,.T.);
#967=ORIENTED_EDGE('',*,*,#966,.T.);
#968=DIRECTION('',(-1.,0.,0.));
#969=VECTOR('',#968,1.);
#970=CARTESIAN_POINT('',(42.0624,14.6646968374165,0.));
#971=LINE('',#970,#969);
#972=CARTESIAN_POINT('',(42.0624,14.6646968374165,0.));
#973=VERTEX_POINT('',#972);
#974=EDGE_CURVE('E214',#973,#965,#971,.T.);
#975=ORIENTED_EDGE('',*,*,#974,.F.);
#976=DIRECTION('',(0.,0.5,0.866025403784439));
#977=VECTOR('',#976,1.);
#978=CARTESIAN_POINT('',(42.0624,7.33234841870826,-12.7));
#979=LINE('',#978,#977);
#980=EDGE_CURVE('E196',#942,#973,#979,.T.);
#981=ORIENTED_EDGE('',*,*,#980,.F.);
#982=ORIENTED_EDGE('',*,*,#943,.T.);
#983=EDGE_LOOP('',(#967,#975,#981,#982));
#984=FACE_BOUND('',#983,.T.);
#985=ADVANCED_FACE('F374',(#984),#959,.F.);
#986=CARTESIAN_POINT('',(42.0624,14.6646968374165,0.));
#987=DIRECTION('',(0.,-0.866025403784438,-0.5));
#988=DIRECTION('',(0.,0.5,-0.866025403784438));
#989=AXIS2_PLACEMENT_3D('',#986,#987,#988);
#990=PLANE('',#989);
#991=DIRECTION('',(0.,-0.5,0.866025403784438));
#992=VECTOR('',#991,1.);
#993=CARTESIAN_POINT('',(0.,14.6646968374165,0.));
#994=LINE('',#993,#992);
#995=CARTESIAN_POINT('',(0.,7.33234841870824,12.7));
#996=VERTEX_POINT('',#995);
#997=EDGE_CURVE('E190',#965,#996,#994,.T.);
#998=ORIENTED_EDGE('',*,*,#997,.T.);
#999=DIRECTION('',(-1.,0.,0.));
#1000=VECTOR('',#999,1.);
#1001=CARTESIAN_POINT('',(42.0624,7.33234841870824,12.7));
#1002=LINE('',#1001,#1000);
#1003=CARTESIAN_POINT('',(42.0624,7.33234841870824,12.7));
#1004=VERTEX_POINT('',#1003);
#1005=EDGE_CURVE('E200',#1004,#996,#1002,.T.);
#1006=ORIENTED_EDGE('',*,*,#1005,.F.);
#1007=DIRECTION('',(0.,-0.5,0.866025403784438));
#1008=VECTOR('',#1007,1.);
#1009=CARTESIAN_POINT('',(42.0624,14.6646968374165,0.));
#1010=LINE('',#1009,#1008);
#1011=EDGE_CURVE('E198',#973,#1004,#1010,.T.);
#1012=ORIENTED_EDGE('',*,*,#1011,.F.);
#1013=ORIENTED_EDGE('',*,*,#974,.T.);
#1014=EDGE_LOOP('',(#998,#1006,#1012,#1013));
#1015=FACE_BOUND('',#1014,.T.);
#1016=ADVANCED_FACE('F366',(#1015),#990,.F.);
#1017=CARTESIAN_POINT('',(42.0624,-7.33234841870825,12.7));
#1018=DIRECTION('',(1.,0.,0.));
#1019=DIRECTION('',(0.,0.,-1.));
#1020=AXIS2_PLACEMENT_3D('',#1017,#1018,#1019);
#1021=PLANE('',#1020);
#1022=DIRECTION('',(0.,-1.,0.));
#1023=VECTOR('',#1022,1.);
#1024=CARTESIAN_POINT('',(42.0624,7.33234841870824,12.7));
#1025=LINE('',#1024,#1023);
#1026=CARTESIAN_POINT('',(42.0624,-7.33234841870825,12.7));
#1027=VERTEX_POINT('',#1026);
#1028=EDGE_CURVE('E186',#1004,#1027,#1025,.T.);
#1029=ORIENTED_EDGE('',*,*,#1028,.T.);
#1030=DIRECTION('',(0.,-0.5,-0.866025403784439));
#1031=VECTOR('',#1030,1.);
#1032=CARTESIAN_POINT('',(42.0624,-7.33234841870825,12.7));
#1033=LINE('',#1032,#1031);
#1034=EDGE_CURVE('E189',#1027,#901,#1033,.T.);
#1035=ORIENTED_EDGE('',*,*,#1034,.T.);
#1036=ORIENTED_EDGE('',*,*,#902,.T.);
#1037=ORIENTED_EDGE('',*,*,#949,.T.);
#1038=ORIENTED_EDGE('',*,*,#980,.T.);
#1039=ORIENTED_EDGE('',*,*,#1011,.T.);
#1040=EDGE_LOOP('',(#1029,#1035,#1036,#1037,#1038,#1039));
#1041=FACE_BOUND('',#1040,.T.);
#1042=CARTESIAN_POINT('',(42.0624,0.,0.));
#1043=DIRECTION('',(1.,0.,0.));
#1044=DIRECTION('',(0.,0.,-1.));
#1045=AXIS2_PLACEMENT_3D('',#1042,#1043,#1044);
#1046=CIRCLE('',#1045,11.1125);
#1047=CARTESIAN_POINT('',(42.0624,0.,11.1125));
#1048=VERTEX_POINT('',#1047);
#1049=EDGE_CURVE('E182',#1048,#1048,#1046,.F.);
#1050=ORIENTED_EDGE('',*,*,#1049,.T.);
#1051=EDGE_LOOP('',(#1050));
#1052=FACE_BOUND('',#1051,.T.);
#1053=ADVANCED_FACE('F362',(#1041,#1052),#1021,.T.);
#1054=CARTESIAN_POINT('',(42.0624,-7.33234841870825,12.7));
#1055=DIRECTION('',(0.,0.866025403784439,-0.5));
#1056=DIRECTION('',(0.,0.5,0.866025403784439));
#1057=AXIS2_PLACEMENT_3D('',#1054,#1055,#1056);
#1058=PLANE('',#1057);
#1059=DIRECTION('',(0.,-0.5,-0.866025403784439));
#1060=VECTOR('',#1059,1.);
#1061=CARTESIAN_POINT('',(0.,-7.33234841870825,12.7));
#1062=LINE('',#1061,#1060);
#1063=CARTESIAN_POINT('',(0.,-7.33234841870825,12.7));
#1064=VERTEX_POINT('',#1063);
#1065=EDGE_CURVE('E203',#1064,#883,#1062,.T.);
#1066=ORIENTED_EDGE('',*,*,#1065,.T.);
#1067=ORIENTED_EDGE('',*,*,#908,.F.);
#1068=ORIENTED_EDGE('',*,*,#1034,.F.);
#1069=DIRECTION('',(-1.,0.,0.));
#1070=VECTOR('',#1069,1.);
#1071=CARTESIAN_POINT('',(42.0624,-7.33234841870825,12.7));
#1072=LINE('',#1071,#1070);
#1073=EDGE_CURVE('E226',#1027,#1064,#1072,.T.);
#1074=ORIENTED_EDGE('',*,*,#1073,.T.);
#1075=EDGE_LOOP('',(#1066,#1067,#1068,#1074));
#1076=FACE_BOUND('',#1075,.T.);
#1077=ADVANCED_FACE('F365',(#1076),#1058,.F.);
#1078=CARTESIAN_POINT('',(0.,-7.33234841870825,12.7));
#1079=DIRECTION('',(1.,0.,0.));
#1080=DIRECTION('',(0.,0.,-1.));
#1081=AXIS2_PLACEMENT_3D('',#1078,#1079,#1080);
#1082=PLANE('',#1081);
#1083=DIRECTION('',(0.,-1.,0.));
#1084=VECTOR('',#1083,1.);
#1085=CARTESIAN_POINT('',(0.,7.33234841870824,12.7));
#1086=LINE('',#1085,#1084);
#1087=EDGE_CURVE('E185',#996,#1064,#1086,.T.);
#1088=ORIENTED_EDGE('',*,*,#1087,.F.);
#1089=ORIENTED_EDGE('',*,*,#997,.F.);
#1090=ORIENTED_EDGE('',*,*,#966,.F.);
#1091=ORIENTED_EDGE('',*,*,#935,.F.);
#1092=ORIENTED_EDGE('',*,*,#886,.F.);
#1093=ORIENTED_EDGE('',*,*,#1065,.F.);
#1094=EDGE_LOOP('',(#1088,#1089,#1090,#1091,#1092,#1093));
#1095=FACE_BOUND('',#1094,.T.);
#1096=ADVANCED_FACE('F368',(#1095),#1082,.F.);
#1097=CARTESIAN_POINT('',(42.0624,7.33234841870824,12.7));
#1098=DIRECTION('',(0.,0.,-1.));
#1099=DIRECTION('',(0.,1.,0.));
#1100=AXIS2_PLACEMENT_3D('',#1097,#1098,#1099);
#1101=PLANE('',#1100);
#1102=CARTESIAN_POINT('',(8.128,0.,12.7));
#1103=DIRECTION('',(0.,0.,1.));
#1104=DIRECTION('',(1.,0.,0.));
#1105=AXIS2_PLACEMENT_3D('',#1102,#1103,#1104);
#1106=CIRCLE('',#1105,6.858);
#1107=CARTESIAN_POINT('',(14.986,0.,12.7));
#1108=VERTEX_POINT('',#1107);
#1109=EDGE_CURVE('E416',#1108,#1108,#1106,.T.);
#1110=ORIENTED_EDGE('',*,*,#1109,.F.);
#1111=EDGE_LOOP('',(#1110));
#1112=FACE_BOUND('',#1111,.T.);
#1113=ORIENTED_EDGE('',*,*,#402,.F.);
#1114=EDGE_LOOP('',(#1113));
#1115=FACE_BOUND('',#1114,.T.);
#1116=ORIENTED_EDGE('',*,*,#1087,.T.);
#1117=ORIENTED_EDGE('',*,*,#1073,.F.);
#1118=ORIENTED_EDGE('',*,*,#1028,.F.);
#1119=ORIENTED_EDGE('',*,*,#1005,.T.);
#1120=EDGE_LOOP('',(#1116,#1117,#1118,#1119));
#1121=FACE_BOUND('',#1120,.T.);
#1122=ADVANCED_FACE('F37',(#1112,#1115,#1121),#1101,.F.);
#1123=CARTESIAN_POINT('',(52.9844,0.,0.));
#1124=DIRECTION('',(-1.,0.,0.));
#1125=DIRECTION('',(0.,0.,1.));
#1126=AXIS2_PLACEMENT_3D('',#1123,#1124,#1125);
#1127=CYLINDRICAL_SURFACE('',#1126,11.1125);
#1128=CARTESIAN_POINT('',(42.0624,0.,11.1125));
#1129=CARTESIAN_POINT('',(42.1761708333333,0.,11.1125));
#1130=CARTESIAN_POINT('',(42.2899416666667,0.,11.1125));
#1131=CARTESIAN_POINT('',(42.5174833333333,0.,11.1125));
#1132=CARTESIAN_POINT('',(42.6312541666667,0.,11.1125));
#1133=CARTESIAN_POINT('',(42.8587958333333,0.,11.1125));
#1134=CARTESIAN_POINT('',(42.9725666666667,0.,11.1125));
#1135=CARTESIAN_POINT('',(43.2001083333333,0.,11.1125));
#1136=CARTESIAN_POINT('',(43.3138791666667,0.,11.1125));
#1137=CARTESIAN_POINT('',(43.5414208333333,0.,11.1125));
#1138=CARTESIAN_POINT('',(43.6551916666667,0.,11.1125));
#1139=CARTESIAN_POINT('',(43.8827333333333,0.,11.1125));
#1140=CARTESIAN_POINT('',(43.9965041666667,0.,11.1125));
#1141=CARTESIAN_POINT('',(44.2240458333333,0.,11.1125));
#1142=CARTESIAN_POINT('',(44.3378166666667,0.,11.1125));
#1143=CARTESIAN_POINT('',(44.5653583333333,0.,11.1125));
#1144=CARTESIAN_POINT('',(44.6791291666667,0.,11.1125));
#1145=CARTESIAN_POINT('',(44.9066708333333,0.,11.1125));
#1146=CARTESIAN_POINT('',(45.0204416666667,0.,11.1125));
#1147=CARTESIAN_POINT('',(45.2479833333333,0.,11.1125));
#1148=CARTESIAN_POINT('',(45.3617541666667,0.,11.1125));
#1149=CARTESIAN_POINT('',(45.5892958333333,0.,11.1125));
#1150=CARTESIAN_POINT('',(45.7030666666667,0.,11.1125));
#1151=CARTESIAN_POINT('',(45.9306083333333,0.,11.1125));
#1152=CARTESIAN_POINT('',(46.0443791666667,0.,11.1125));
#1153=CARTESIAN_POINT('',(46.2719208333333,0.,11.1125));
#1154=CARTESIAN_POINT('',(46.3856916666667,0.,11.1125));
#1155=CARTESIAN_POINT('',(46.6132333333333,0.,11.1125));
#1156=CARTESIAN_POINT('',(46.7270041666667,0.,11.1125));
#1157=CARTESIAN_POINT('',(46.9545458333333,0.,11.1125));
#1158=CARTESIAN_POINT('',(47.0683166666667,0.,11.1125));
#1159=CARTESIAN_POINT('',(47.2958583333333,0.,11.1125));
#1160=CARTESIAN_POINT('',(47.4096291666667,0.,11.1125));
#1161=CARTESIAN_POINT('',(47.6371708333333,0.,11.1125));
#1162=CARTESIAN_POINT('',(47.7509416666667,0.,11.1125));
#1163=CARTESIAN_POINT('',(47.9784833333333,0.,11.1125));
#1164=CARTESIAN_POINT('',(48.0922541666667,0.,11.1125));
#1165=CARTESIAN_POINT('',(48.3197958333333,0.,11.1125));
#1166=CARTESIAN_POINT('',(48.4335666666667,0.,11.1125));
#1167=CARTESIAN_POINT('',(48.6611083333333,0.,11.1125));
#1168=CARTESIAN_POINT('',(48.7748791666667,0.,11.1125));
#1169=CARTESIAN_POINT('',(49.0024208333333,0.,11.1125));
#1170=CARTESIAN_POINT('',(49.1161916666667,0.,11.1125));
#1171=CARTESIAN_POINT('',(49.3437333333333,0.,11.1125));
#1172=CARTESIAN_POINT('',(49.4575041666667,0.,11.1125));
#1173=CARTESIAN_POINT('',(49.6850458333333,0.,11.1125));
#1174=CARTESIAN_POINT('',(49.7988166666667,0.,11.1125));
#1175=CARTESIAN_POINT('',(50.0263583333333,0.,11.1125));
#1176=CARTESIAN_POINT('',(50.1401291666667,0.,11.1125));
#1177=CARTESIAN_POINT('',(50.3676708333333,0.,11.1125));
#1178=CARTESIAN_POINT('',(50.4814416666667,0.,11.1125));
#1179=CARTESIAN_POINT('',(50.7089833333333,0.,11.1125));
#1180=CARTESIAN_POINT('',(50.8227541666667,0.,11.1125));
#1181=CARTESIAN_POINT('',(51.0502958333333,0.,11.1125));
#1182=CARTESIAN_POINT('',(51.1640666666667,0.,11.1125));
#1183=CARTESIAN_POINT('',(51.3916083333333,0.,11.1125));
#1184=CARTESIAN_POINT('',(51.5053791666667,0.,11.1125));
#1185=CARTESIAN_POINT('',(51.7329208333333,0.,11.1125));
#1186=CARTESIAN_POINT('',(51.8466916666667,0.,11.1125));
#1187=CARTESIAN_POINT('',(52.0742333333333,0.,11.1125));
#1188=CARTESIAN_POINT('',(52.1880041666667,0.,11.1125));
#1189=CARTESIAN_POINT('',(52.4155458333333,0.,11.1125));
#1190=CARTESIAN_POINT('',(52.5293166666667,0.,11.1125));
#1191=CARTESIAN_POINT('',(52.7568583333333,0.,11.1125));
#1192=CARTESIAN_POINT('',(52.8706291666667,0.,11.1125));
#1193=CARTESIAN_POINT('',(52.9844,0.,11.1125));
#1194=B_SPLINE_CURVE_WITH_KNOTS('',3,(#1128,#1129,#1130,#1131,#1132,#1133,#1134,#1135,#1136,
#1137,#1138,#1139,#1140,#1141,#1142,#1143,#1144,#1145,#1146,#1147,#1148,#1149,#1150,#1151,#1152,
#1153,#1154,#1155,#1156,#1157,#1158,#1159,#1160,#1161,#1162,#1163,#1164,#1165,#1166,#1167,#1168,
#1169,#1170,#1171,#1172,#1173,#1174,#1175,#1176,#1177,#1178,#1179,#1180,#1181,#1182,#1183,#1184,
#1185,#1186,#1187,#1188,#1189,#1190,#1191,#1192,#1193),.UNSPECIFIED.,.F.,.F.,(4,2,2,2,2,2,2,2,2,
2,2,2,2,2,2,2,2,2,2,2,2,2,2,2,2,2,2,2,2,2,2,2,4),(0.,0.341312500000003,0.682624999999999,
1.0239375,1.36525000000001,1.7065625,2.047875,2.3891875,2.7305,3.0718125,3.413125,3.7544375,
4.09575,4.4370625,4.778375,5.1196875,5.461,5.8023125,6.143625,6.4849375,6.82625,7.1675625,
7.508875,7.8501875,8.1915,8.5328125,8.874125,9.2154375,9.55675,9.8980625,10.239375,10.5806875,
10.922),.UNSPECIFIED.);
#1195=EDGE_CURVE('BSEAM358',#1048,#660,#1194,.T.);
#1196=ORIENTED_EDGE('',*,*,#1049,.F.);
#1197=ORIENTED_EDGE('',*,*,#661,.F.);
#1198=ORIENTED_EDGE('',*,*,#1195,.T.);
#1199=ORIENTED_EDGE('',*,*,#1195,.F.);
#1200=EDGE_LOOP('',(#1196,#1198,#1197,#1199));
#1201=FACE_BOUND('',#1200,.T.);
#1202=ADVANCED_FACE('F358',(#1201),#1127,.T.);
#1203=CARTESIAN_POINT('',(13.6906,0.,2.6797));
#1204=DIRECTION('',(0.,0.,-1.));
#1205=DIRECTION('',(-1.,0.,0.));
#1206=AXIS2_PLACEMENT_3D('',#1203,#1204,#1205);
#1207=PLANE('',#1206);
#1208=CARTESIAN_POINT('',(8.128,0.,2.6797));
#1209=DIRECTION('',(0.,0.,1.));
#1210=DIRECTION('',(1.,0.,0.));
#1211=AXIS2_PLACEMENT_3D('',#1208,#1209,#1210);
#1212=CIRCLE('',#1211,6.55797879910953);
#1213=EDGE_CURVE('E426',#846,#825,#1212,.T.);
#1214=ORIENTED_EDGE('',*,*,#1213,.T.);
#1215=ORIENTED_EDGE('',*,*,#826,.F.);
#1216=CARTESIAN_POINT('',(8.128,0.,2.6797));
#1217=DIRECTION('',(0.,0.,1.));
#1218=DIRECTION('',(1.,0.,0.));
#1219=AXIS2_PLACEMENT_3D('',#1216,#1217,#1218);
#1220=CIRCLE('',#1219,5.5626);
#1221=EDGE_CURVE('E421',#854,#817,#1220,.T.);
#1222=ORIENTED_EDGE('',*,*,#1221,.F.);
#1223=ORIENTED_EDGE('',*,*,#855,.F.);
#1224=EDGE_LOOP('',(#1214,#1215,#1222,#1223));
#1225=FACE_BOUND('',#1224,.T.);
#1226=ADVANCED_FACE('F253',(#1225),#1207,.F.);
#1227=CARTESIAN_POINT('',(8.128,0.,12.7));
#1228=DIRECTION('',(0.,0.,1.));
#1229=DIRECTION('',(1.,0.,0.));
#1230=AXIS2_PLACEMENT_3D('',#1227,#1228,#1229);
#1231=CONICAL_SURFACE('',#1230,6.858,0.0299323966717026);
#1232=ORIENTED_EDGE('',*,*,#1109,.T.);
#1233=EDGE_LOOP('',(#1232));
#1234=FACE_BOUND('',#1233,.T.);
#1235=ORIENTED_EDGE('',*,*,#1213,.F.);
#1236=ORIENTED_EDGE('',*,*,#847,.F.);
#1237=EDGE_LOOP('',(#1235,#1236));
#1238=FACE_BOUND('',#1237,.T.);
#1239=ADVANCED_FACE('F251',(#1234,#1238),#1231,.F.);
#1240=CARTESIAN_POINT('',(8.128,0.,12.7));
#1241=DIRECTION('',(0.,0.,1.));
#1242=DIRECTION('',(1.,0.,0.));
#1243=AXIS2_PLACEMENT_3D('',#1240,#1241,#1242);
#1244=CYLINDRICAL_SURFACE('',#1243,5.56260000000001);
#1245=ORIENTED_EDGE('',*,*,#818,.F.);
#1246=CARTESIAN_POINT('',(8.128,0.,-2.6797));
#1247=DIRECTION('',(0.,0.,-1.));
#1248=DIRECTION('',(0.,1.,0.));
#1249=AXIS2_PLACEMENT_3D('',#1246,#1247,#1248);
#1250=CIRCLE('',#1249,5.56260000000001);
#1251=EDGE_CURVE('E456',#730,#858,#1250,.T.);
#1252=ORIENTED_EDGE('',*,*,#1251,.T.);
#1253=ORIENTED_EDGE('',*,*,#859,.F.);
#1254=ORIENTED_EDGE('',*,*,#1221,.T.);
#1255=EDGE_LOOP('',(#1245,#1252,#1253,#1254));
#1256=FACE_BOUND('',#1255,.T.);
#1257=ADVANCED_FACE('F245',(#1256),#1244,.F.);
#1258=CARTESIAN_POINT('',(13.6906,0.,-2.6797));
#1259=DIRECTION('',(0.,0.,1.));
#1260=DIRECTION('',(0.,-1.,0.));
#1261=AXIS2_PLACEMENT_3D('',#1258,#1259,#1260);
#1262=PLANE('',#1261);
#1263=CARTESIAN_POINT('',(8.128,0.,-2.6797));
#1264=DIRECTION('',(0.,0.,-1.));
#1265=DIRECTION('',(0.,1.,0.));
#1266=AXIS2_PLACEMENT_3D('',#1263,#1264,#1265);
#1267=CIRCLE('',#1266,6.55797879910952);
#1268=EDGE_CURVE('E450',#722,#720,#1267,.T.);
#1269=ORIENTED_EDGE('',*,*,#1268,.T.);
#1270=ORIENTED_EDGE('',*,*,#865,.F.);
#1271=ORIENTED_EDGE('',*,*,#1251,.F.);
#1272=ORIENTED_EDGE('',*,*,#731,.F.);
#1273=EDGE_LOOP('',(#1269,#1270,#1271,#1272));
#1274=FACE_BOUND('',#1273,.T.);
#1275=ADVANCED_FACE('F250',(#1274),#1262,.F.);
#1276=CARTESIAN_POINT('',(8.128,0.,-12.7));
#1277=DIRECTION('',(0.,0.,-1.));
#1278=DIRECTION('',(0.,1.,0.));
#1279=AXIS2_PLACEMENT_3D('',#1276,#1277,#1278);
#1280=CONICAL_SURFACE('',#1279,6.858,0.0299323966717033);
#1281=ORIENTED_EDGE('',*,*,#925,.T.);
#1282=EDGE_LOOP('',(#1281));
#1283=FACE_BOUND('',#1282,.T.);
#1284=ORIENTED_EDGE('',*,*,#1268,.F.);
#1285=ORIENTED_EDGE('',*,*,#723,.F.);
#1286=EDGE_LOOP('',(#1284,#1285));
#1287=FACE_BOUND('',#1286,.T.);
#1288=ADVANCED_FACE('F293',(#1283,#1287),#1280,.F.);
#1289=CARTESIAN_POINT('',(0.,0.,0.));
#1290=DIRECTION('',(-1.,0.,0.));
#1291=DIRECTION('',(0.,0.,1.));
#1292=AXIS2_PLACEMENT_3D('',#1289,#1290,#1291);
#1293=CYLINDRICAL_SURFACE('',#1292,5.5499);
#1294=CARTESIAN_POINT('',(45.0596,0.,0.));
#1295=DIRECTION('',(-1.,0.,0.));
#1296=DIRECTION('',(0.,0.,1.));
#1297=AXIS2_PLACEMENT_3D('',#1294,#1295,#1296);
#1298=CIRCLE('',#1297,5.54990000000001);
#1299=CARTESIAN_POINT('',(45.0596,0.,5.54990000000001));
#1300=VERTEX_POINT('',#1299);
#1301=EDGE_CURVE('E513',#1300,#1300,#1298,.T.);
#1302=ORIENTED_EDGE('',*,*,#1301,.F.);
#1303=EDGE_LOOP('',(#1302));
#1304=FACE_BOUND('',#1303,.T.);
#1305=ORIENTED_EDGE('',*,*,#463,.T.);
#1306=ORIENTED_EDGE('',*,*,#60,.T.);
#1307=ORIENTED_EDGE('',*,*,#248,.T.);
#1308=ORIENTED_EDGE('',*,*,#589,.T.);
#1309=ORIENTED_EDGE('',*,*,#317,.T.);
#1310=ORIENTED_EDGE('',*,*,#101,.T.);
#1311=EDGE_LOOP('',(#1305,#1306,#1307,#1308,#1309,#1310));
#1312=FACE_BOUND('',#1311,.T.);
#1313=ADVANCED_FACE('F287',(#1304,#1312),#1293,.F.);
#1314=CARTESIAN_POINT('',(45.059599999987,5.5499,0.));
#1315=DIRECTION('',(1.,0.,0.));
#1316=DIRECTION('',(0.,0.,-1.));
#1317=AXIS2_PLACEMENT_3D('',#1314,#1315,#1316);
#1318=PLANE('',#1317);
#1319=ORIENTED_EDGE('',*,*,#1301,.T.);
#1320=EDGE_LOOP('',(#1319));
#1321=FACE_BOUND('',#1320,.T.);
#1322=CARTESIAN_POINT('',(45.0595999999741,0.,0.));
#1323=DIRECTION('',(-1.,0.,0.));
#1324=DIRECTION('',(0.,0.,1.));
#1325=AXIS2_PLACEMENT_3D('',#1322,#1323,#1324);
#1326=CIRCLE('',#1325,6.31567883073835);
#1327=CARTESIAN_POINT('',(45.0595999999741,0.,6.31567883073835));
#1328=VERTEX_POINT('',#1327);
#1329=EDGE_CURVE('E508',#1328,#1328,#1326,.T.);
#1330=ORIENTED_EDGE('',*,*,#1329,.F.);
#1331=EDGE_LOOP('',(#1330));
#1332=FACE_BOUND('',#1331,.T.);
#1333=ADVANCED_FACE('F292',(#1321,#1332),#1318,.T.);
#1334=CARTESIAN_POINT('',(52.9844,0.,0.));
#1335=DIRECTION('',(1.,0.,0.));
#1336=DIRECTION('',(0.,0.,-1.));
#1337=AXIS2_PLACEMENT_3D('',#1334,#1335,#1336);
#1338=CONICAL_SURFACE('',#1337,6.73100000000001,0.0523598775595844);
#1339=ORIENTED_EDGE('',*,*,#1329,.T.);
#1340=EDGE_LOOP('',(#1339));
#1341=FACE_BOUND('',#1340,.T.);
#1342=ORIENTED_EDGE('',*,*,#672,.F.);
#1343=EDGE_LOOP('',(#1342));
#1344=FACE_BOUND('',#1343,.T.);
#1345=ADVANCED_FACE('F496',(#1341,#1344),#1338,.F.);
#1346=CARTESIAN_POINT('',(26.79065,0.,0.));
#1347=DIRECTION('',(1.,0.,0.));
#1348=DIRECTION('',(0.,0.,-1.));
#1349=AXIS2_PLACEMENT_3D('',#1346,#1347,#1348);
#1350=PLANE('',#1349);
#1351=CARTESIAN_POINT('',(26.79065,0.,0.));
#1352=DIRECTION('',(-1.,0.,0.));
#1353=DIRECTION('',(0.,0.,1.));
#1354=AXIS2_PLACEMENT_3D('',#1351,#1352,#1353);
#1355=CIRCLE('',#1354,5.5499);
#1356=CARTESIAN_POINT('',(26.79065,0.,5.5499));
#1357=VERTEX_POINT('',#1356);
#1358=EDGE_CURVE('E518',#1357,#1357,#1355,.T.);
#1359=ORIENTED_EDGE('',*,*,#1358,.F.);
#1360=EDGE_LOOP('',(#1359));
#1361=FACE_BOUND('',#1360,.T.);
#1362=ORIENTED_EDGE('',*,*,#42,.T.);
#1363=EDGE_LOOP('',(#1362));
#1364=FACE_BOUND('',#1363,.T.);
#1365=ADVANCED_FACE('F295',(#1361,#1364),#1350,.T.);
#1366=ORIENTED_EDGE('',*,*,#1358,.T.);
#1367=EDGE_LOOP('',(#1366));
#1368=FACE_BOUND('',#1367,.T.);
#1369=ORIENTED_EDGE('',*,*,#523,.T.);
#1370=ORIENTED_EDGE('',*,*,#93,.T.);
#1371=ORIENTED_EDGE('',*,*,#384,.T.);
#1372=ORIENTED_EDGE('',*,*,#643,.T.);
#1373=ORIENTED_EDGE('',*,*,#176,.T.);
#1374=ORIENTED_EDGE('',*,*,#73,.T.);
#1375=EDGE_LOOP('',(#1369,#1370,#1371,#1372,#1373,#1374));
#1376=FACE_BOUND('',#1375,.T.);
#1377=ADVANCED_FACE('F149',(#1368,#1376),#1293,.F.);
#1378=CLOSED_SHELL('',(#46,#84,#107,#253,#389,#528,#648,#676,#696,#872,#912,#954,#985,#1016,
#1053,#1077,#1096,#1122,#1202,#1226,#1239,#1257,#1275,#1288,#1313,#1333,#1345,#1365,#1377));
#1379=MANIFOLD_SOLID_BREP('B2',#1378);
#1380=ADVANCED_BREP_SHAPE_REPRESENTATION('',(#18,#1379),#14);
#1381=SHAPE_DEFINITION_REPRESENTATION(#9,#1380);
ENDSEC;
END-ISO-10303-21;
